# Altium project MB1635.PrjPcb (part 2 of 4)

## Sheet Power_Board.SchDoc: Board power
size A3; Project: STM32MP15-DISCO; Date: Not used; ApprovedBy: Not used; CheckedBy: Not used; Author: Not used; CompanyName: STMicroelectronics; DrawnBy: Not used; Engineer: Not used; Organization: Not used; Address1: Not used; Address2: Not used; Address3: Not used; Address4: Not used; DocumentNumber: 5; Revision: Not used; SheetNumber: 5; SheetTotal: 17

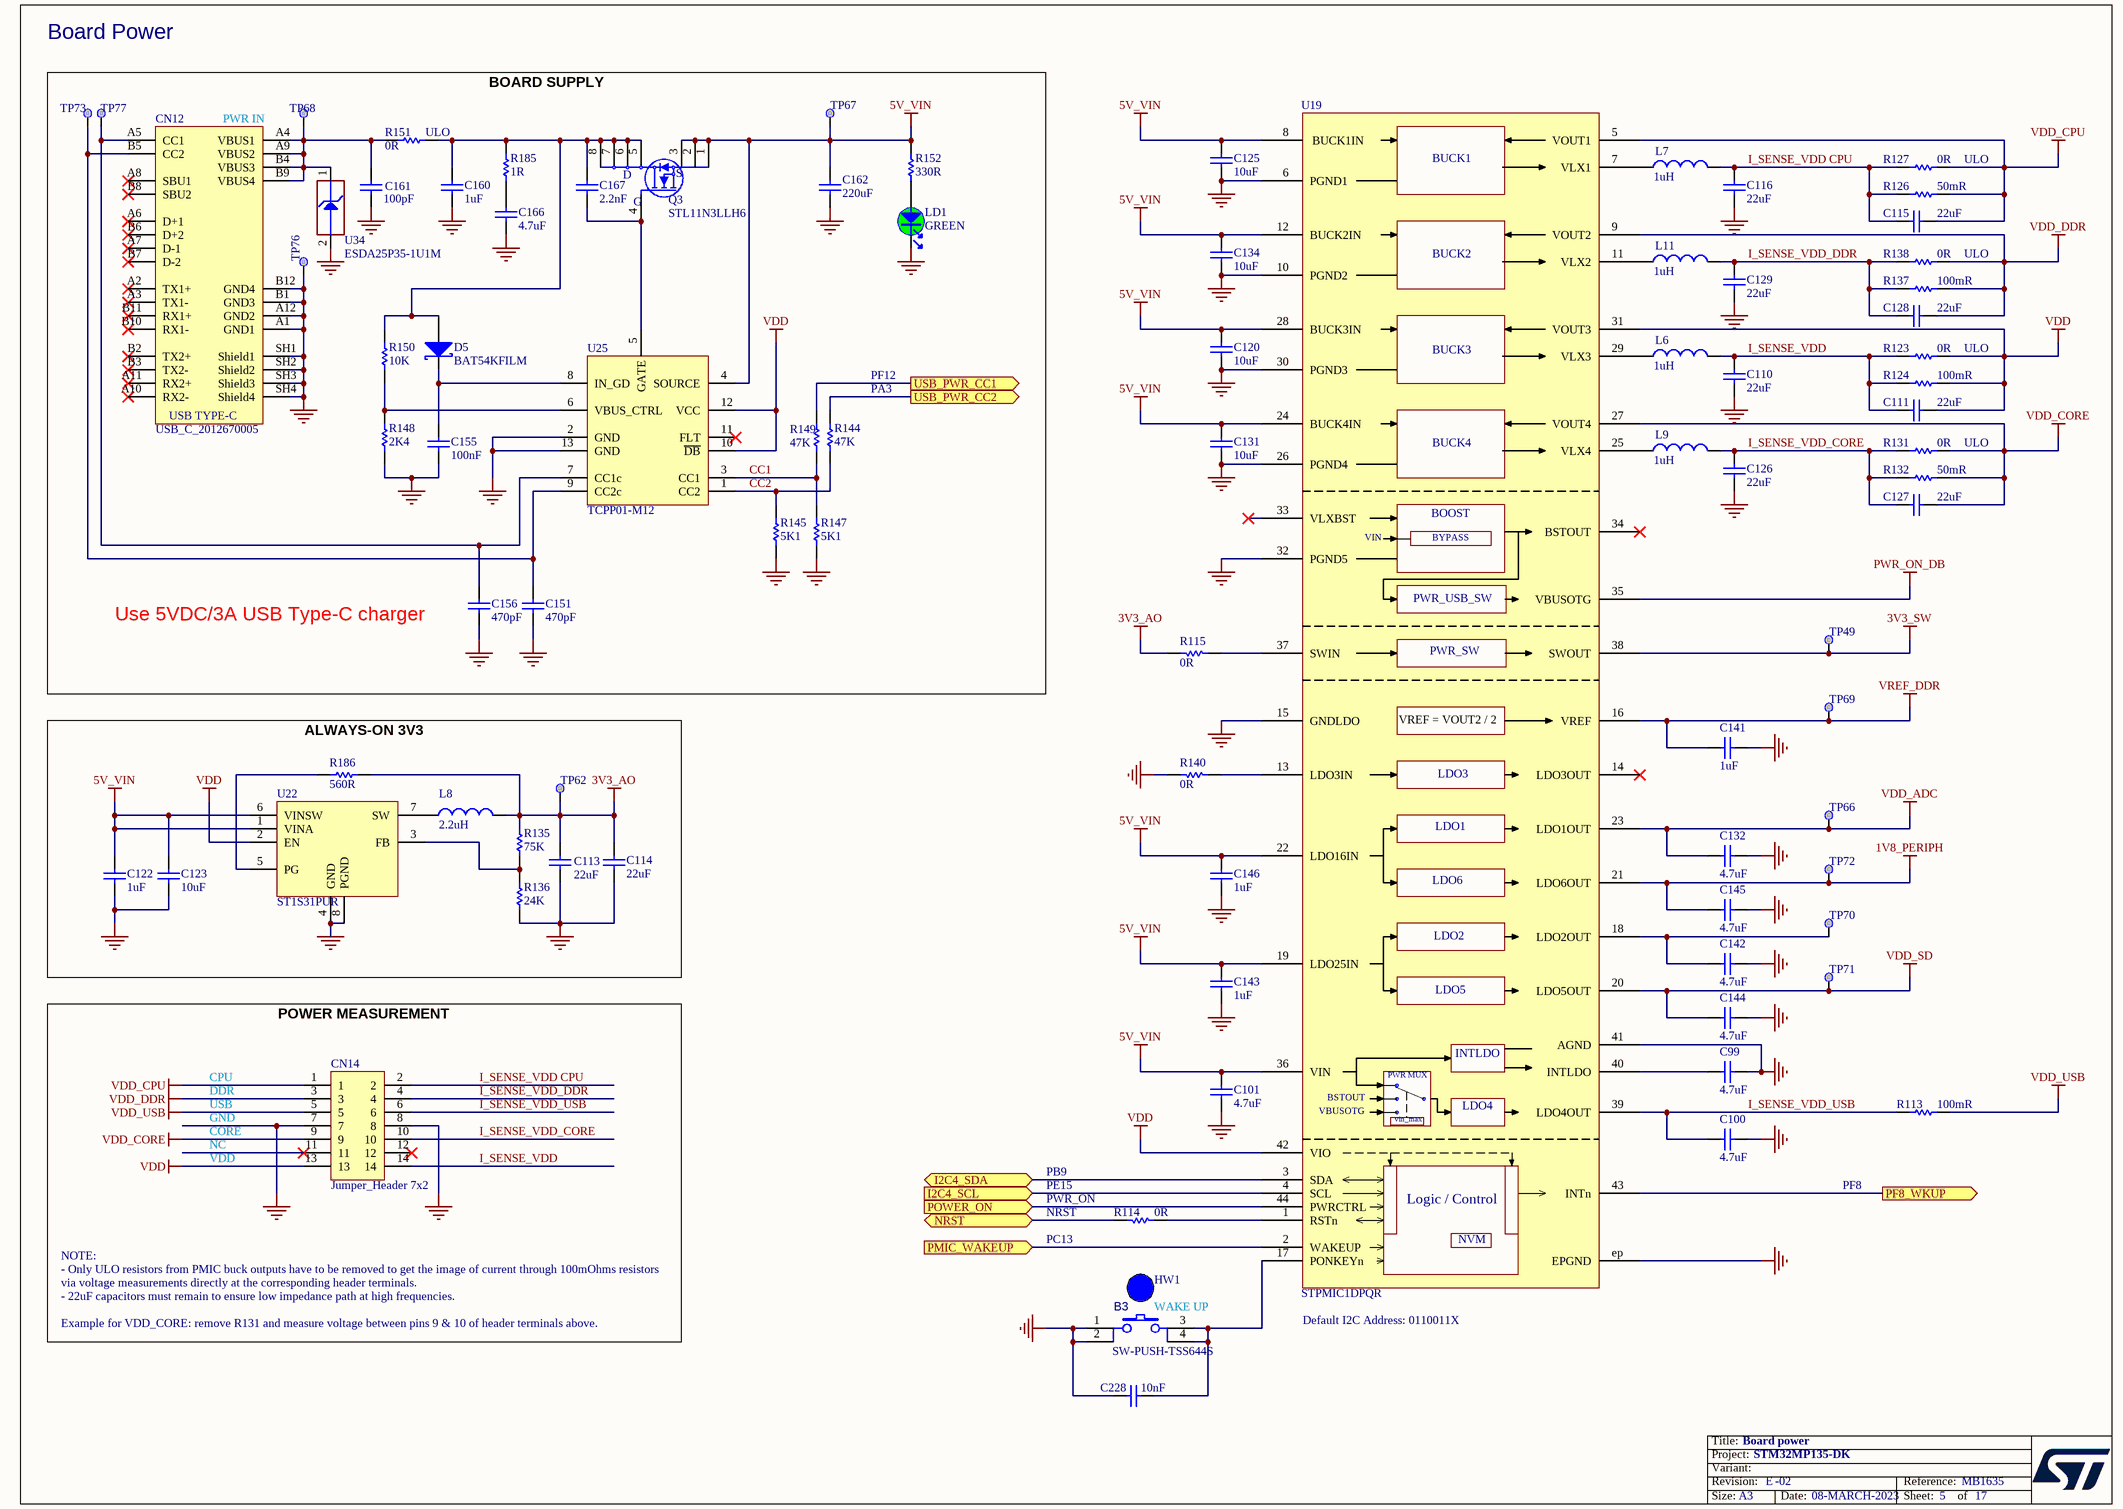
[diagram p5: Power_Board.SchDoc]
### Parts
B3  value SW-PUSH-TSS644S  [SWI_KNITTER_TSS644S]  (hidden comment: SW_PUSH_SMD)
C99  value 4.7uF  [C0402]  (hidden comment: Capacitor)
C100  value 4.7uF  [C0402]  (hidden comment: Capacitor)
C101  value 4.7uF  [C0402]  (hidden comment: Capacitor)
C110  value 22uF  [C0603]  (hidden comment: Capacitor)
C111  value 22uF  [C0603]  (hidden comment: Capacitor)
C113  value 22uF  [C0603]  (hidden comment: Capacitor)
C114  value 22uF  [C0603]  (hidden comment: Capacitor)
C115  value 22uF  [C0603]  (hidden comment: Capacitor)
C116  value 22uF  [C0603]  (hidden comment: Capacitor)
C120  value 10uF  [C0603]  (hidden comment: Capacitor)
C122  value 1uF  [C0402]  (hidden comment: Capacitor)
C123  value 10uF  [C0603]  (hidden comment: Capacitor)
C125  value 10uF  [C0603]  (hidden comment: Capacitor)
C126  value 22uF  [C0603]  (hidden comment: Capacitor)
C127  value 22uF  [C0603]  (hidden comment: Capacitor)
C128  value 22uF  [C0603]  (hidden comment: Capacitor)
C129  value 22uF  [C0603]  (hidden comment: Capacitor)
C131  value 10uF  [C0603]  (hidden comment: Capacitor)
C132  value 4.7uF  [C0402]  (hidden comment: Capacitor)
C134  value 10uF  [C0603]  (hidden comment: Capacitor)
C141  value 1uF  [C0402]  (hidden comment: Capacitor)
C142  value 4.7uF  [C0402]  (hidden comment: Capacitor)
C143  value 1uF  [C0402]  (hidden comment: Capacitor)
C144  value 4.7uF  [C0402]  (hidden comment: Capacitor)
C145  value 4.7uF  [C0402]  (hidden comment: Capacitor)
C146  value 1uF  [C0402]  (hidden comment: Capacitor)
C151  value 470pF  [C0402]  (hidden comment: Capacitor)
C155  value 100nF  [C0603]  (hidden comment: Capacitor)
C156  value 470pF  [C0402]  (hidden comment: Capacitor)
C160  value 1uF  [C0402]  (hidden comment: Capacitor)
C161  value 100pF  [C0402]  (hidden comment: Capacitor)
C162  value 220uF  [C1206_H1P6]  (hidden comment: Capacitor)
C166  value 4.7uF  [C0603]  (hidden comment: Capacitor)
C167  value 2.2nF  [C0603_H0P8]  (hidden comment: Capacitor)
C228  value 10nF  [C0402]  (hidden comment: Capacitor)
CN12  value USB_C_2012670005  [CON_USB-TYPEC_MOLEX_2012670005]  (hidden comment: USB_TYPE_C_Receptacle)
CN14  value Jumper_Header 7x2  [CON_SAMTEC_TSW-107-07-X-D]  (hidden comment: Header 7x2)
D5  value BAT54KFILM  [DIO_SOD523_1A_2K]  (hidden comment: SCHOTTKY_1A_2K)
HW1  Blue Hat  (value not drawn)  (mechanical)
L6  value 1uH  [IND_2520_TOKO_DFE252012P]  (hidden comment: IND_1uH_42mohm_3.2A)
L7  value 1uH  [IND_2520_TOKO_DFE252012P]  (hidden comment: IND_1uH_42mohm_3.2A)
L8  value 2.2uH  [IND_4025_WURTH_74404043022A]  (hidden comment: Inductor)
L9  value 1uH  [IND_2520_TOKO_DFE252012P]  (hidden comment: IND_1uH_42mohm_3.2A)
L11  value 1uH  [IND_2520_TOKO_DFE252012P]  (hidden comment: IND_1uH_42mohm_3.2A)
LD1  value GREEN  [LED_0603_GREEN]  (hidden comment: LED_green)
Q3  STL11N3LLH6  [MOS_POWERFLAT_3P3X3P3_P065]
R113  value 100mR  [R0603]  (hidden comment: Resistor)
R114  value 0R  [R0402]  (hidden comment: Resistor)
R115  value 0R  [R0402]  (hidden comment: Resistor)
R123  value 0R  [R0603]  (hidden comment: Resistor)
R124  value 100mR  [R0603]  (hidden comment: Resistor)
R126  value 50mR  [R0603]  (hidden comment: Resistor)
R127  value 0R  [R0603]  (hidden comment: Resistor)
R131  value 0R  [R0603]  (hidden comment: Resistor)
R132  value 50mR  [R0603]  (hidden comment: Resistor)
R135  value 75K  [R0402]  (hidden comment: Resistor)
R136  value 24K  [R0402]  (hidden comment: Resistor)
R137  value 100mR  [R0603]  (hidden comment: Resistor)
R138  value 0R  [R0603]  (hidden comment: Resistor)
R140  value 0R  [R0402]  (hidden comment: Resistor)
R144  value 47K  [R0402]  (hidden comment: Resistor)
R145  value 5K1  [R0402]  (hidden comment: Resistor)
R147  value 5K1  [R0402]  (hidden comment: Resistor)
R148  value 2K4  [R0402]  (hidden comment: Resistor)
R149  value 47K  [R0402]  (hidden comment: Resistor)
R150  value 10K  [R0402]  (hidden comment: Resistor)
R151  value 0R  [R0603]  (hidden comment: Resistor)
R152  value 330R  [R0402]  (hidden comment: Resistor)
R185  value 1R  [R0603]  (hidden comment: Resistor)
R186  value 560R  [R0402]  (hidden comment: Resistor)
TP49  Test Point  [TP_SMD_1MM]  (value not drawn)  (no BOM)
TP62  Test Point  [TP_SMD_1MM]  (value not drawn)  (no BOM)
TP66  Test Point  [TP_SMD_1MM]  (value not drawn)  (no BOM)
TP67  Test Point  [TP_SMD_1MM]  (value not drawn)  (no BOM)
TP68  Test Point  [TP_SMD_2MM]  (value not drawn)  (no BOM)
TP69  Test Point  [TP_SMD_1MM]  (value not drawn)  (no BOM)
TP70  Test Point  [TP_SMD_1MM]  (value not drawn)  (no BOM)
TP71  Test Point  [TP_SMD_1MM]  (value not drawn)  (no BOM)
TP72  Test Point  [TP_SMD_1MM]  (value not drawn)  (no BOM)
TP73  Test Point  [TP_SMD_1MM]  (value not drawn)  (no BOM)
TP76  Test Point  [TP_SMD_2MM]  (value not drawn)  (no BOM)
TP77  Test Point  [TP_SMD_1MM]  (value not drawn)  (no BOM)
U19  value STPMIC1DPQR  [ICC_WFQFN44-EPAD_5X6_P040]  (hidden comment: STPMU1)
U22  ST1S31PUR  [ICC_VFDFPN8-EPAD_3X3_P065]
U25  TCPP01-M12  [ICC_QFN12L-EPAD_3X3_P050]
U34  value ESDA25P35-1U1M  [ESD_QFN1610_2N_1K_2A]  (hidden comment: ESD-TRANSIL)

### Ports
I2C4_SCL (in), I2C4_SDA (bidir), NRST (bidir), PF8_WKUP (out), PMIC_WAKEUP (in), POWER_ON (in), USB_PWR_CC1 (out), USB_PWR_CC2 (out)

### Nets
1V8_PERIPH: C145.2 TP72.1 U19.21(LDO6OUT)
3V3_AO: C113.2 C114.2 L8.2 R115.1 R135.2 R186.2 TP62.1
3V3_SW: TP49.1 U19.38(SWOUT)
5V_VIN: C101.2 C120.2 C122.2 C123.2 C125.2 C131.2 C134.2 C143.2 C146.2 C162.1 Q3.1(S) Q3.2(S) Q3.3(S) R152.2 TP67.1 U19.8(BUCK1IN) U19.12(BUCK2IN) U19.19(LDO25IN) U19.22(LDO16IN) U19.24(BUCK4IN) U19.28(BUCK3IN) U19.36(VIN) U22.1(VINA) U22.6(VINSW) U25.4(SOURCE)
GND: B3.1 B3.2 C99.2 C100.1 C101.1 C110.1 C113.1 C114.1 C116.1 C120.1 C122.1 C123.1 C125.1 C126.1 C129.1 C131.1 C132.1 C134.1 C141.1 C142.1 C143.1 C144.1 C145.1 C146.1 C151.1 C155.2 C156.1 C160.2 C161.1 C162.2 C166.1 C228.1 CN12.A1(GND1) CN12.A12(GND2) CN12.B1(GND3) CN12.B12(GND4) CN12.SH1(Shield1) CN12.SH2(Shield2) CN12.SH3(Shield3) CN12.SH4(Shield4) CN14.7 CN14.8 LD1.2 R136.1 R140.1 R145.1 R147.1 R148.1 TP76.1 U19.6(PGND1) U19.10(PGND2) U19.15(GNDLDO) U19.26(PGND4) U19.30(PGND3) U19.32(PGND5) U19.41(AGND) U19.ep(EPGND) U22.4(GND) U22.8(PGND) U25.2(GND) U25.13(GND) U34.2(GND)
PWR_ON_DB: U19.35(VBUSOTG)
VDD: C111.2 CN14.13 R123.2 R124.2 U19.31(VOUT3) U19.42(VIO) U22.2(EN) U25.10(~{DB}) U25.12(VCC)
VDD_ADC: C132.2 TP66.1 U19.23(LDO1OUT)
VDD_CORE: C127.2 CN14.9 R131.2 R132.2 U19.27(VOUT4)
VDD_CPU: C115.2 CN14.1 R126.2 R127.2 U19.5(VOUT1)
VDD_DDR: C128.2 CN14.3 R137.2 R138.2 U19.9(VOUT2)
VDD_SD: C144.2 TP71.1 U19.20(LDO5OUT)
VDD_USB: CN14.5 R113.2
VREF_DDR: C141.2 TP69.1 U19.16(VREF)
CC1: R147.2 R149.1 U25.3(CC1)
CC2: R144.1 R145.2 U25.1(CC2)
I2C4_SCL: U19.4(SCL) ; port I2C4_SCL
I2C4_SDA: U19.3(SDA) ; port I2C4_SDA
I_SENSE_VDD: C110.2 C111.1 CN14.14 L6.2 R123.1 R124.1
I_SENSE_VDD CPU: C115.1 C116.2 CN14.2 L7.2 R126.1 R127.1
I_SENSE_VDD_CORE: C126.2 C127.1 CN14.10 L9.2 R131.1 R132.1
I_SENSE_VDD_DDR: C128.1 C129.2 CN14.4 L11.2 R137.1 R138.1
I_SENSE_VDD_USB: C100.2 CN14.6 R113.1 U19.39(LDO4OUT)
NRST: R114.1 ; port NRST
PF8_WKUP: U19.43(INTn) ; port PF8_WKUP
PMIC_WAKEUP: U19.2(WAKEUP) ; port PMIC_WAKEUP
POWER_ON: U19.44(PWRCTRL) ; port POWER_ON
USB_PWR_CC1: R149.2 ; port USB_PWR_CC1
USB_PWR_CC2: R144.2 ; port USB_PWR_CC2
NetB3_3: B3.3 B3.4 C228.2 U19.17(PONKEYn)
NetC99_1: C99.1 U19.40(INTLDO)
NetC142_2: C142.2 TP70.1 U19.18(LDO2OUT)
NetC151_2: C151.2 CN12.B5(CC2) TP73.1 U25.9(CC2c)
NetC155_1: C155.1 D5.2(K) U25.8(IN_GD)
NetC156_2: C156.2 CN12.A5(CC1) TP77.1 U25.7(CC1c)
NetC160_1: C160.1 C167.2 D5.1(A) Q3.5(D) Q3.6(D) Q3.7(D) Q3.8(D) R150.2 R151.2 R185.2
NetC161_2: C161.2 CN12.A4(VBUS1) CN12.A9(VBUS2) CN12.B4(VBUS3) CN12.B9(VBUS4) R151.1 TP68.1 U34.1(IO1)
NetC166_2: C166.2 R185.1
NetC167_1: C167.1 Q3.4(G) U25.5(GATE)
NetL6_1: L6.1 U19.29(VLX3)
NetL7_1: L7.1 U19.7(VLX1)
NetL8_1: L8.1 U22.7(SW)
NetL9_1: L9.1 U19.25(VLX4)
NetL11_1: L11.1 U19.11(VLX2)
NetLD1_1: LD1.1 R152.1
NetR114_2: R114.2 U19.1(RSTn)
NetR115_2: R115.2 U19.37(SWIN)
NetR135_1: R135.1 R136.2 U22.3(FB)
NetR140_2: R140.2 U19.13(LDO3IN)
NetR148_2: R148.2 R150.1 U25.6(VBUS_CTRL)
NetR186_1: R186.1 U22.5(PG)

Not connected (* = marked no-connect by the designer): CN12 A2(TX1+)* A3(TX1-)* A6(D+1)* A7(D-1)* A8(SBU1)* A10(RX2-)* A11(RX2+)* B2(TX2+)* B3(TX2-)* B6(D+2)* B7(D-2)* B8(SBU2)* B10(RX1-)* B11(RX1+)*; CN14 11* 12*; U19 14(LDO3OUT)* 33(VLXBST)* 34(BSTOUT)*; U25 11(FLT)*

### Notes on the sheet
- Board Power
- (near CN12) PWR IN
- (near R151) ULO
- ULO
- PF12
- PA3
- Use 5VDC/3A USB Type-C charger
- BOARD SUPPLY
- ALWAYS-ON 3V3
- CPU
- DDR
- USB
- GND
- VDD
- CORE
- NC
- PB9
- PE15
- PF8
- NRST
- (near R114) PWR_ON
- PC13
- NOTE:
  - Only ULO resistors from PMIC buck outputs have to be removed to get the image of current through 100mOhms resistors via voltage measurements directly at the corresponding header terminals.
  - 22uF capacitors must remain to ensure low impedance path at high frequencies.
  Example for VDD_CORE: remove R131 and measure voltage between pins 9 & 10 of header terminals above.
- (near B3) WAKE UP
- Default I2C Address: 0110011X
- (near CN14) POWER MEASUREMENT

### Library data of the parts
B3 = MCD-02417: Push Button, NO, 0.05A, 12V, 2.6N, SMD, 9.0x6.2mm, T=7.3mm, changeable caps KTSC-6xx; Part_Type: Misc; Manufacturer_Part_Number: TSS644S; Manufacturer: KNITTER-SWITCH; Part_Preference: Recommended; Component_Country_Of_Origin: China; ShowFields: YES; ID: 4523
C99-C101 C132 C142 C144 C145 = MCD-01356: Capacitor, MLCC, 4.7uF, 6V3, X5R, +/-20%, 0402, T=0.5mm; Manufacturer_Part_Number: GRM155R60J475ME47; Manufacturer: MURATA; Part_Preference: Recommended; Order_Code_RS: 814-5230; Component_Country_Of_Origin: Japan; ShowFields: YES; ID: 3456
C110 C116 C126 C129 = MCD-00100: Capacitor, MLCC, 22uF, 6V3, X5R, +/-20%, 0603, T=0.8mm; Manufacturer_Part_Number: GRM188R60J226MEA0J; Manufacturer: MURATA; Part_Preference: Recommended; Component_Country_Of_Origin: Japan; ShowFields: YES; ID: 2766
C111 C113-C115 C127 C128 = MCD-00100: Capacitor, MLCC, 22uF, 6V3, X5R, +/-20%, 0603, T=0.8mm; Part_Preference: Recommended; Manufacturer: MURATA; Manufacturer_Part_Number: GRM188R60J226MEA0J; Component_Country_Of_Origin: Japan; ShowFields: YES; ID: 2766
C120 C125 C131 C134 = MCD-00099: Capacitor, MLCC, 10uF, 10V, X5R, +/-10%, 0603, T=0.8mm; Manufacturer_Part_Number: GRM188R61A106KE69D; Manufacturer: MURATA; Part_Preference: Recommended; Order_Code_RS: 170-6168; Component_Country_Of_Origin: Japan; ShowFields: YES; ID: 2770
C122 = MCD-00095: Capacitor, MLCC, 1uF, 25V, X5R, +/-10%, 0402, T=0.5mm; Part_Preference: Recommended; Manufacturer: MURATA; Manufacturer_Part_Number: GRM155R61E105KA12; Order_Code_RS: 846-7287; Component_Country_Of_Origin: Japan; ShowFields: YES; ID: 2772
C123 = MCD-00099: Capacitor, MLCC, 10uF, 10V, X5R, +/-10%, 0603, T=0.8mm; Part_Preference: Recommended; Manufacturer: MURATA; Manufacturer_Part_Number: GRM188R61A106KE69D; Order_Code_RS: 170-6168; Component_Country_Of_Origin: Japan; ShowFields: YES; ID: 2770
C141 C143 C146 C160 = MCD-00095: Capacitor, MLCC, 1uF, 25V, X5R, +/-10%, 0402, T=0.5mm; Manufacturer_Part_Number: GRM155R61E105KA12; Manufacturer: MURATA; Part_Preference: Recommended; Order_Code_RS: 846-7287; Component_Country_Of_Origin: Japan; ShowFields: YES; ID: 2772
C151 C156 = MCD-00724: Capacitor, MLCC, 470pF, 50V, NPO, +/-5%, 0402, T=0.5mm; Manufacturer_Part_Number: CC0402JRNPO9BN471; Manufacturer: YAGEO; Part_Preference: Recommended; Order_Code_RS: 199-2186; Component_Country_Of_Origin: China; ShowFields: YES; ID: 3023
C155 = MCD-01099: Capacitor, MLCC, 100nF, 50V, X7R, +/-10%, 0603, T=0.8mm; Manufacturer_Part_Number: CC0603KRX7R9BB104; Manufacturer: YAGEO; Part_Preference: Recommended; BMS_Part_Number: 9142278; Order_Code_RS: 669-8767; Component_Country_Of_Origin: China; ShowFields: YES; ID: 3397
C161 = MCD-00205: Capacitor, MLCC, 100pF, 50V, NPO, +/-5%, 0402, T=0.5mm; Manufacturer_Part_Number: CC0402JRNPO9BN101; Manufacturer: YAGEO; Part_Preference: Recommended; Component_Country_Of_Origin: China; ShowFields: YES; ID: 2658
C162 = MCD-00104: Capacitor, MLCC, 220uF, 6V3, X5R, +/-20%, 1206, T=1.6mm; Manufacturer_Part_Number: GRM31CR60J227ME11; Manufacturer: MURATA; Part_Preference: Recommended; Order_Code_RS: 170-6396; Component_Country_Of_Origin: Japan; ShowFields: YES; ID: 2764
C166 = MCD-02196: Capacitor, MLCC, 4.7uF, 25V, X5R, +/-10%, 0603, T=0.8mm; Manufacturer_Part_Number: C1608X5R1E475K080AC; Manufacturer: TDK; Part_Preference: Recommended; Order_Code_RS: 9159158; Component_Country_Of_Origin: Unknown; ShowFields: YES; ID: 4296
C167 = MCD-02457: Capacitor, MLCC, 2.2nF, 50V, C0G/NPO, +/-5%, 0603, T=0,8mm; Part_Preference: Recommended; Manufacturer: YAGEO; Manufacturer_Part_Number: CC0603JRNPO9BN222; Order_Code_RS: 200-6484; Component_Country_Of_Origin: China; ShowFields: YES; ID: 4563
C228 = MCD-02198: Capacitor, MLCC, 10nF, 50V, X7R, +/-10%, 0402, T=0.5mm; Manufacturer_Part_Number: CC0402KRX7R9BB103; Manufacturer: YAGEO; Part_Preference: Recommended; Order_Code_RS: 6169644; Component_Country_Of_Origin: China; ShowFields: YES; ID: 4298
CN12 = MCD-02421: USB_TypeC, 24 pins, RA, SMD, T=3.71mm (USB Certified 3.1); Part_Type: Connector; Manufacturer_Part_Number: 2012670005; Manufacturer: MOLEX; Part_Preference: Recommended; Order_Code_RS: 176-8434; Component_Country_Of_Origin: Unknown; ShowFields: YES; ID: 4527
CN14 = MCD-02123: Header, 7x2, 2.54mm, VR, TH, T=5.84mm/2.54mm; Part_Preference: Recommended; Part_Type: Connector; Manufacturer: SAMTEC; Manufacturer_Part_Number: TSW-107-07-G-D; Component_Country_Of_Origin: China, Costa Rica, Malaysia, United States, Vietnam; ShowFields: YES; ID: 4223
D5 = MCD-01677: Small signal Schottky diodes; BMS_Part_Number: 9151123; Part_Preference: Recommended; Part_Type: Diode; Manufacturer: STMICROELECTRONICS; Manufacturer_HQ_COO: EU; Component_Country_Of_Origin: China; ShowFields: YES; ID: 3777
HW1 = MCD-02136: Switch hat, blue, For KTSC-62B; Part_Type: Misc; Part_Preference: Recommended; Manufacturer: APEM INC; Manufacturer_Part_Number: AKTSC62B; Order_Code_RS: 378-6779; Component_Country_Of_Origin: Unknown; ShowFields: YES; ID: 4236
L6 L7 L9 L11 = MCD-01122: Inductor, 1uH, +/-20%, 4.3A max, 0R042, 2520, T=1.2mm; Manufacturer_Part_Number: DFE252012P-1ROM=P2; Manufacturer: MURATA; Part_Preference: Recommended; Component_Country_Of_Origin: Japan; ShowFields: YES; ID: 3373
L8 = MCD-02242: Inductor, 2.2uH, +/-30%, 3,83A, 0R023, 4x4mm, T=2.5mm; Part_Preference: Recommended; Manufacturer: WURTH ELEKTRONIK; Manufacturer_Part_Number: 74404043022A; Component_Country_Of_Origin: Unknown; ShowFields: YES; ID: 4342
LD1 = MCD-00050: LED, Green, 0603; Part_Type: Display; Manufacturer_Part_Number: 19-213SYGC/S530-E2/TR8; Manufacturer: EVERLIGHT; Part_Preference: Forbidden; Component_Country_Of_Origin: China; ShowFields: YES; ID: 2542
Q3 = MCD-01810: N-channel 30 V, 6 mΩ typ, 11 A STripFET™ H6, Power MOSFET in a PowerFLAT™ 3.3x3.3 package; Part_Type: IC; Manufacturer: STMICROELECTRONICS; BMS_Part_Number: 9153561; Part_Preference: Recommended; Manufacturer_HQ_COO: EU; Component_Country_Of_Origin: China; ShowFields: YES; ID: 3910
R113 R124 R137 = MCD-02234: Resistor, 100mR, 0603, +/- 1%, 1/3W; Part_Preference: Recommended; Manufacturer: PANASONIC; Manufacturer_Part_Number: ERJ-3BWFR100V; Order_Code_RS: 763-8731; Component_Country_Of_Origin: Japan; ShowFields: YES; ID: 4334
R114 R115 R140 = MCD-00052: Resistor, 0R, 0402, +/-5%, 1/16W; Manufacturer_Part_Number: RC0402JR-070RL; Manufacturer: YAGEO; Part_Preference: Recommended; Order_Code_RS: 618-5804; Component_Country_Of_Origin: China; ShowFields: YES; ID: 2540
R123 R127 R131 R138 = MCD-00181: Resistor, 0R, 0603, +/- 0.5mR, 1/4W; Part_Preference: Recommended; Manufacturer: ROHM; Manufacturer_Part_Number: PMR03EZPJ000; Component_Country_Of_Origin: Philippines, Thailand; ShowFields: YES; ID: 2691
R126 R132 = MCD-02233: Resistor, 50mR, 0603, +/-1%, 1/3W; Part_Preference: Recommended; Manufacturer: PANASONIC; Manufacturer_Part_Number: ERJ-3BWFR050V; Order_Code_RS: RA; Component_Country_Of_Origin: Japan; ShowFields: YES; ID: 4333
R135 = MCD-00521: Resistor, 75K, 0402, +/-1%, 1/16W; Part_Preference: Recommended; Manufacturer: YAGEO; Manufacturer_Part_Number: RC0402FR-0775KL; Component_Country_Of_Origin: China; ShowFields: YES; ID: 3220
R136 = MCD-00435: Resistor, 24K, 0402, +/-1%, 1/16W; Part_Preference: Recommended; Manufacturer: YAGEO; Manufacturer_Part_Number: RC0402FR-0724KL; Component_Country_Of_Origin: China; ShowFields: YES; ID: 2845
R144 R149 = MCD-00063: Resistor, 47K, 0402, +/-1%, 1/16W; Manufacturer_Part_Number: RC0402FR-0747KL; Manufacturer: YAGEO; Part_Preference: Recommended; Component_Country_Of_Origin: China; ShowFields: YES; ID: 2528
R145 R147 = MCD-00333: Resistor, 5K1, 0402, +/-1%, 1/16W; Manufacturer_Part_Number: RC0402FR-075K1L; Manufacturer: YAGEO; Part_Preference: Recommended; Component_Country_Of_Origin: China; ShowFields: YES; ID: 2944
R148 = MCD-00433: Resistor, 2K4, 0402, +/-1%, 1/16W; Part_Preference: Recommended; Manufacturer: YAGEO; Manufacturer_Part_Number: RC0402FR-072K4L; Component_Country_Of_Origin: China; ShowFields: YES; ID: 2843
R150 = MCD-00053: Resistor, 10K, 0402, +/-1%, 1/16W; BMS_Part_Number: 9131590; Part_Preference: Recommended; Manufacturer: YAGEO; Manufacturer_Part_Number: RC0402FR-0710KL; Component_Country_Of_Origin: China; ShowFields: YES; ID: 2539
R151 = MCD-00181: Resistor, 0R, 0603, +/- 0.5mR, 1/4W; Manufacturer_Part_Number: PMR03EZPJ000; Manufacturer: ROHM; Part_Preference: Recommended; Component_Country_Of_Origin: Philippines, Thailand; ShowFields: YES; ID: 2691
R152 = MCD-00062: Resistor, 330R, 0402, +/-1%, 1/16W; Manufacturer_Part_Number: RC0402FR-07330RL; Manufacturer: YAGEO; Part_Preference: Recommended; Component_Country_Of_Origin: China; ShowFields: YES; ID: 2529
R185 = MCD-01512: Resistor, 1R, 0603, +/-1%, 1/10W; Part_Preference: Recommended; Manufacturer: YAGEO; Manufacturer_Part_Number: RC0603FR-071RL; Component_Country_Of_Origin: China; ShowFields: YES; ID: 3612
R186 = MCD-00489: Resistor, 560R, 0402, +/-1%, 1/16W; Part_Preference: Recommended; Manufacturer: YAGEO; Manufacturer_Part_Number: RC0402FR-07560RL; Component_Country_Of_Origin: China; ShowFields: YES; ID: 2789
TP49 TP62 TP66 TP67 TP69-TP73 TP77 = MCD-00074: Test Point 1mm; Part_Type: Misc; Part_Preference: Recommended; ShowFields: YES; ID: 2518
TP68 TP76 = MCD-00177: Test Point 2mm; Part_Type: Misc; Part_Preference: Recommended; ShowFields: YES; ID: 2690
U19 = MCD-02275: ST PMIC: 4 step-down +1 advanced boost SMPS, 6 LDOs, 2 pwr switches, DDR Vref, NVM option 'D' for IO@3.3V; Part_Preference: Recommended; Part_Type: IC; Manufacturer: STMICROELECTRONICS; Component_Country_Of_Origin: Philippines; ShowFields: YES; ID: 4375
U22 = MCD-02243: 3A DC step-down switching regulator 1,5MHz; Part_Preference: Recommended; Part_Type: IC; Manufacturer: STMICROELECTRONICS; Manufacturer_HQ_COO: EU; Component_Country_Of_Origin: Malaysia; ShowFields: YES; ID: 4343
U25 = MCD-01809: USB Type-C Port Protection for USB Power Delivery, PPS compliant; BMS_Part_Number: 9151145; Part_Preference: Recommended; Part_Type: IC; Manufacturer: STMICROELECTRONICS; Manufacturer_HQ_COO: EU; Component_Country_Of_Origin: Malaysia; ShowFields: YES; ID: 3909
U34 = MCD-01207: High power Transient voltage suppressor:25V/35A EOS and ESD transients protection.; BMS_Part_Number: 9179045; Part_Preference: Recommended; Part_Type: Diode; Manufacturer: STMICROELECTRONICS; Manufacturer_HQ_COO: EU; Component_Country_Of_Origin: China; ShowFields: YES; ID: 3289

## Sheet ST-Link_V3E.SchDoc: ST-LINK V3E
size A3; Project: STLink V3 Embedded Prototype; BOM Version: A-01; Date: Not used; ApprovedBy: Not used; CheckedBy: Not used; Author: Not used; CompanyName: STMicroelectronics; DrawnBy: Not used; Engineer: Not used; Organization: Not used; Address1: Not used; Address2: Not used; Address3: Not used; Address4: Not used; DocumentNumber: 17; Revision: Not used; SheetNumber: 17; SheetTotal: 17

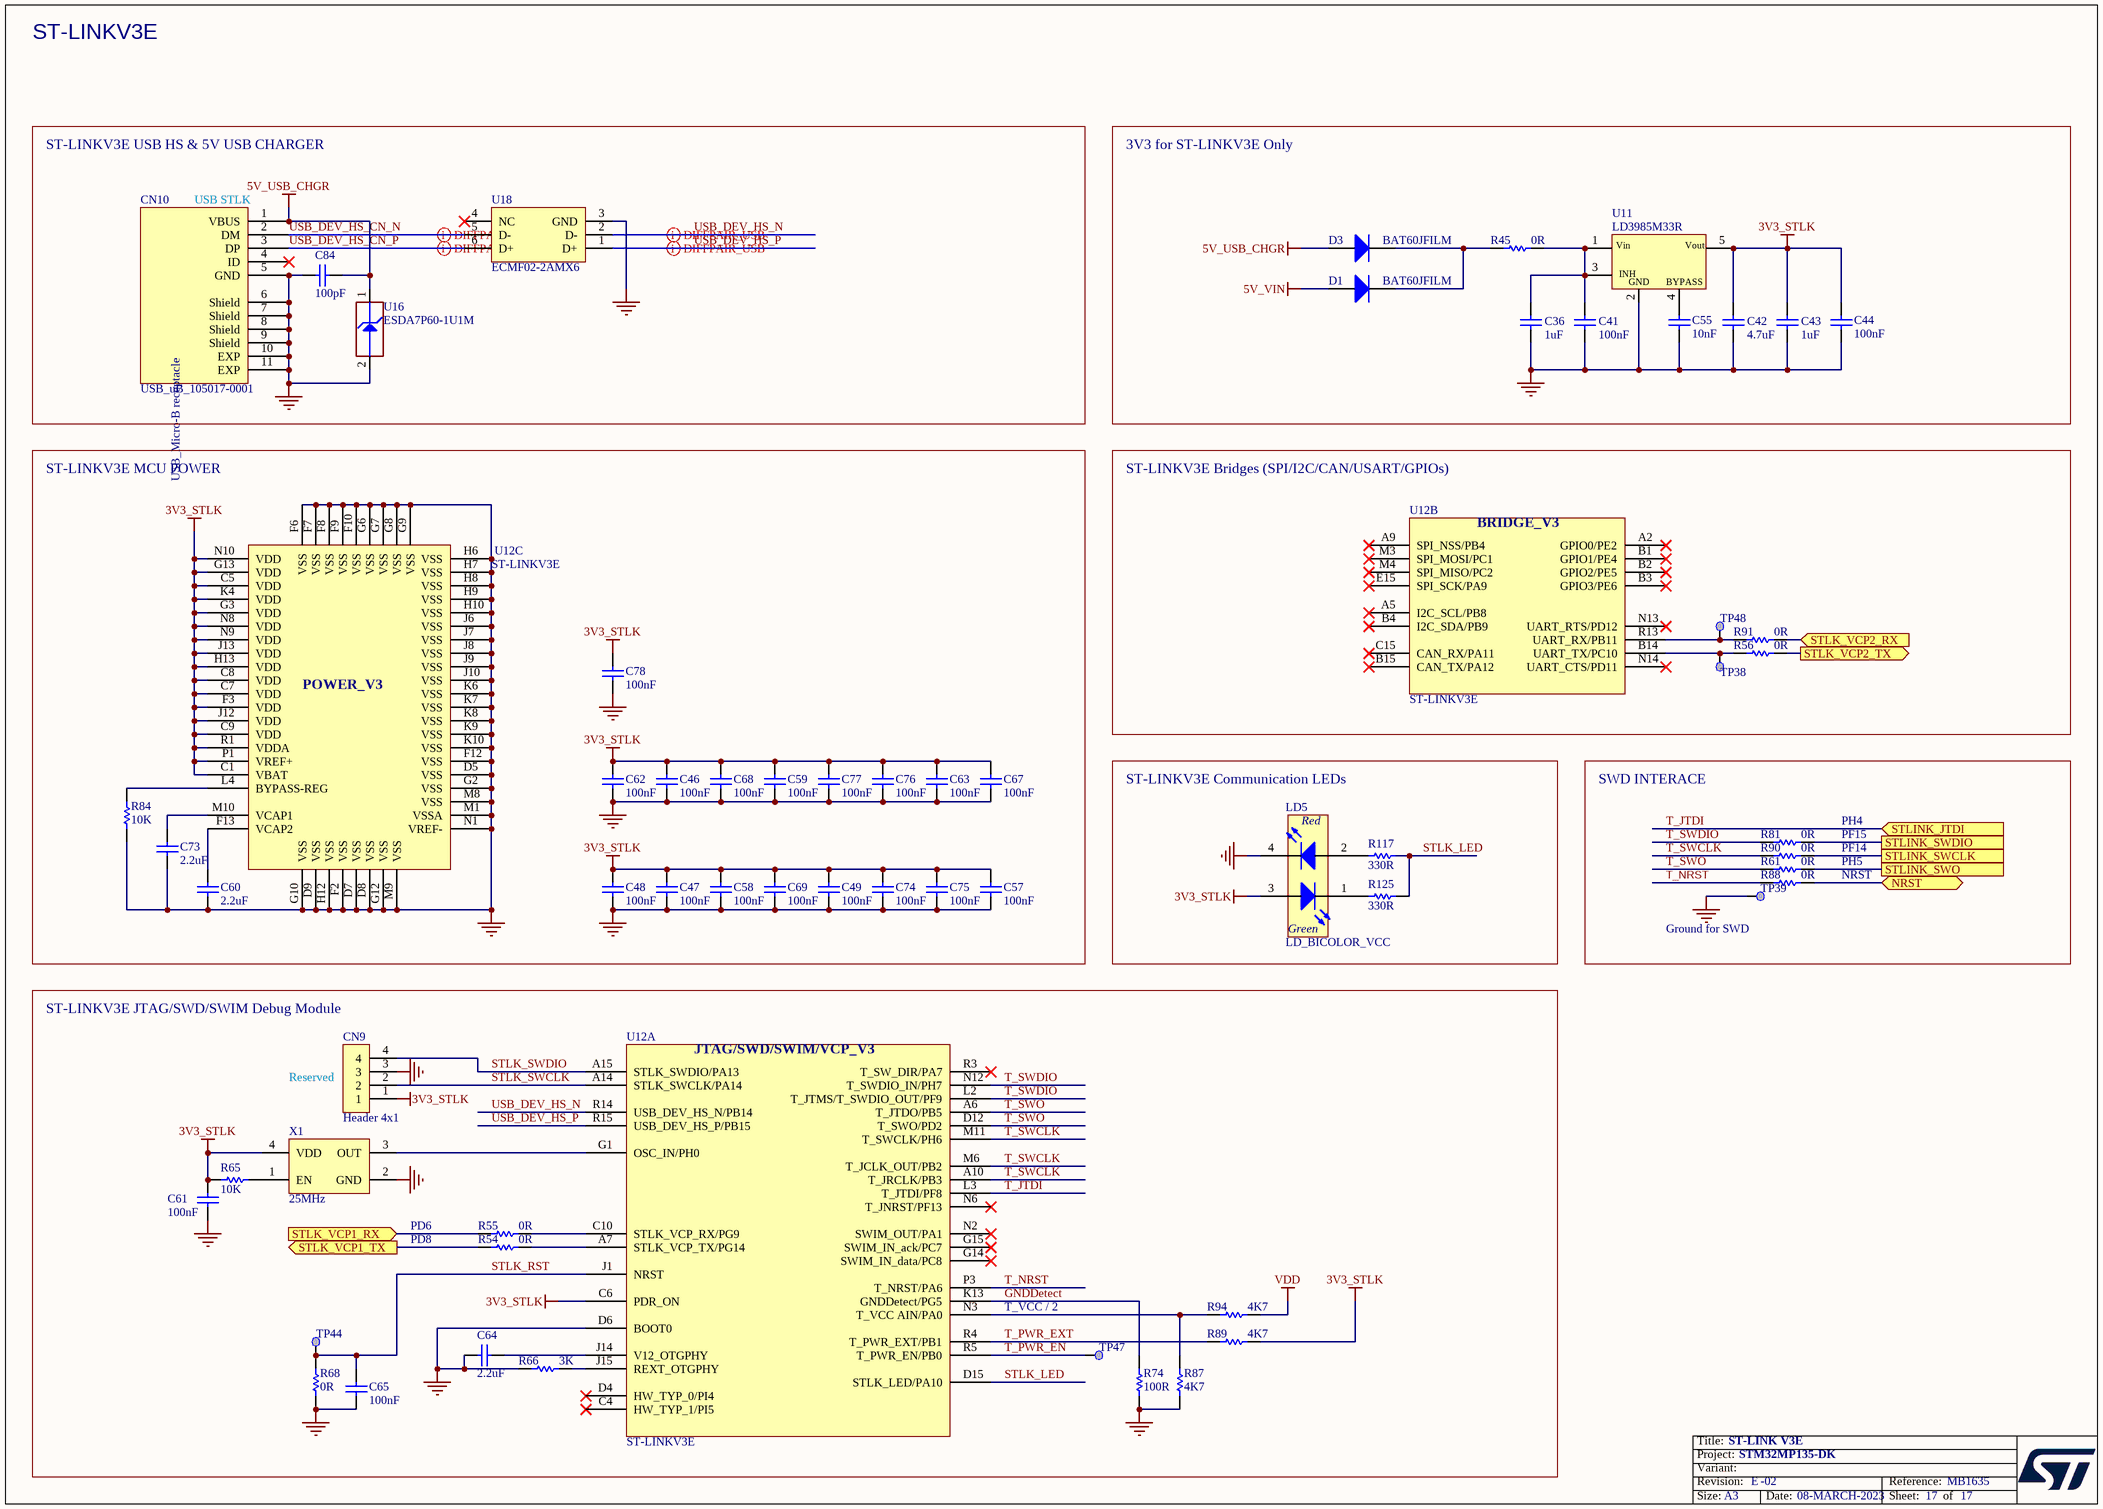
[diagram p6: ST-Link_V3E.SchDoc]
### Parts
C36  value 1uF  [C0402]  (hidden comment: Capacitor)
C41  value 100nF  [C0402]  (hidden comment: Capacitor)
C42  value 4.7uF  [C0402]  (hidden comment: Capacitor)
C43  value 1uF  [C0402]  (hidden comment: Capacitor)
C44  value 100nF  [C0402]  (hidden comment: Capacitor)
C46  value 100nF  [C0402]  (hidden comment: Capacitor)
C47  value 100nF  [C0402]  (hidden comment: Capacitor)
C48  value 100nF  [C0402]  (hidden comment: Capacitor)
C49  value 100nF  [C0402]  (hidden comment: Capacitor)
C55  value 10nF  [C0402]  (hidden comment: Capacitor)
C57  value 100nF  [C0402]  (hidden comment: Capacitor)
C58  value 100nF  [C0402]  (hidden comment: Capacitor)
C59  value 100nF  [C0402]  (hidden comment: Capacitor)
C60  value 2.2uF  [C0201_H0P5]  (hidden comment: Capacitor)
C61  value 100nF  [C0402]  (hidden comment: Capacitor)
C62  value 100nF  [C0402]  (hidden comment: Capacitor)
C63  value 100nF  [C0402]  (hidden comment: Capacitor)
C64  value 2.2uF  [C0201_H0P5]  (hidden comment: Capacitor)
C65  value 100nF  [C0402]  (hidden comment: Capacitor)
C67  value 100nF  [C0402]  (hidden comment: Capacitor)
C68  value 100nF  [C0402]  (hidden comment: Capacitor)
C69  value 100nF  [C0402]  (hidden comment: Capacitor)
C73  value 2.2uF  [C0201_H0P5]  (hidden comment: Capacitor)
C74  value 100nF  [C0402]  (hidden comment: Capacitor)
C75  value 100nF  [C0402]  (hidden comment: Capacitor)
C76  value 100nF  [C0402]  (hidden comment: Capacitor)
C77  value 100nF  [C0402]  (hidden comment: Capacitor)
C78  value 100nF  [C0402]  (hidden comment: Capacitor)
C84  value 100pF  [C0402]  (hidden comment: Capacitor)
CN9  Header 4x1  [CON_SAMTEC_TSW-104-07-G-S]
CN10  value USB_uB_105017-0001  [CON_USBMICROB_MOLEX_105017-0001_H2P90]  (hidden comment: USB_uB_105017.0001)
D1  BAT60JFILM  [DIO_SOD323]
D3  BAT60JFILM  [DIO_SOD323]
LD5  LD_BICOLOR_VCC  [LED_BI-GR_CMD67-22]
R45  value 0R  [R0402]  (hidden comment: Resistor)
R54  value 0R  [R0402]  (hidden comment: Resistor)
R55  value 0R  [R0402]  (hidden comment: Resistor)
R56  value 0R  [R0402]  (hidden comment: Resistor)
R61  value 0R  [R0402]  (hidden comment: Resistor)
R65  value 10K  [R0402]  (hidden comment: Resistor)
R66  value 3K  [R0402]  (hidden comment: Resistor)
R68  value 0R  [R0402]  (hidden comment: Resistor)
R74  value 100R  [R0402]  (hidden comment: Resistor)
R81  value 0R  [R0402]  (hidden comment: Resistor)
R84  value 10K  [R0402]  (hidden comment: Resistor)
R87  value 4K7  [R0402]  (hidden comment: Resistor)
R88  value 0R  [R0402]  (hidden comment: Resistor)
R89  value 4K7  [R0402]  (hidden comment: Resistor)
R90  value 0R  [R0402]  (hidden comment: Resistor)
R91  value 0R  [R0402]  (hidden comment: Resistor)
R94  value 4K7  [R0402]  (hidden comment: Resistor)
R117  value 330R  [R0402]  (hidden comment: Resistor)
R125  value 330R  [R0402]  (hidden comment: Resistor)
TP38  Test Point  [TP_SMD_1MM]  (value not drawn)  (no BOM)
TP39  Test Point  [TP_SMD_1MM]  (value not drawn)  (no BOM)
TP44  Test Point  [TP_SMD_1MM]  (value not drawn)  (no BOM)
TP47  Test Point  [TP_SMD_1MM]  (value not drawn)  (no BOM)
TP48  Test Point  [TP_SMD_1MM]  (value not drawn)  (no BOM)
U11  LD3985M33R  [REG_SOT23-5L]
U12  ST-LINKV3E  [ICC_UFBGA201_176+25_10X10_P065]  (parts A,B,C of 3)
U16  value ESDA7P60-1U1M  [ESD_QFN2_1P6X1_P125]  (hidden comment: ESD-TRANSIL)
U18  ECMF02-2AMX6  [ESD_QFN-6L_1P7X1P5_P050]
X1  value 25MHz  [OSC_NDK_NZ2520SB_4P]  (hidden comment: OSCILLATOR_4_PINS)

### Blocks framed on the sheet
ST-LINKV3E USB HS & 5V USB CHARGER: C84 CN10 U16 U18
3V3 for ST-LINKV3E Only: C36 C41-C44 C55 D1 D3 R45 U11
ST-LINKV3E MCU POWER: C46-C49 C57-C60 C62 C63 C67-C69 C73-C78 R84 U12
ST-LINKV3E Bridges (SPI/I2C/CAN/USART/GPIOs): R56 R91 TP38 TP48 U12
ST-LINKV3E Communication LEDs: LD5 R117 R125
SWD INTERACE: R61 R81 R88 R90 TP39
ST-LINKV3E JTAG/SWD/SWIM Debug Module: C61 C64 C65 CN9 R54 R55 R65 R66 R68 R74 R87 R89 R94 TP44 TP47 U12 X1

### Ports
NRST (bidir), STLINK_JTDI (in), STLINK_SWCLK, STLINK_SWDIO, STLINK_SWO, STLK_VCP1_RX (in), STLK_VCP1_TX (out), STLK_VCP2_RX (in), STLK_VCP2_TX (out)

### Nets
3V3_STLK: C42.2 C43.2 C44.2 C46.2 C47.2 C48.2 C49.2 C57.2 C58.2 C59.2 C61.2 C62.2 C63.2 C67.2 C68.2 C69.2 C74.2 C75.2 C76.2 C77.2 C78.2 CN9.1 LD5.3(YellowGreen_anode) R65.1 R89.1 U11.5(Vout) U12.C1(VBAT) U12.C5(VDD) U12.C6(PDR_ON) U12.C7(VDD) U12.C8(VDD) U12.C9(VDD) U12.F3(VDD) U12.G3(VDD) U12.G13(VDD) U12.H13(VDD) U12.J12(VDD) U12.J13(VDD) U12.K4(VDD) U12.N8(VDD) U12.N9(VDD) U12.N10(VDD) U12.P1(VREF+) U12.R1(VDDA) X1.4(VDD)
5V_USB_CHGR: C84.2 CN10.1(VBUS) D3.1(A) U16.1(IO1)
5V_VIN: D1.1(A)
GND: C36.2 C41.1 C42.1 C43.1 C44.1 C46.1 C47.1 C48.1 C49.1 C55.1 C57.1 C58.1 C59.1 C60.1 C61.1 C62.1 C63.1 C64.1 C65.1 C67.1 C68.1 C69.1 C73.1 C74.1 C75.1 C76.1 C77.1 C78.1 C84.1 CN9.3 CN10.5(GND) CN10.6(Shield) CN10.7(Shield) CN10.8(Shield) CN10.9(Shield) CN10.10(EXP) CN10.11(EXP) LD5.4(RED_cathode) R66.1 R68.2 R74.1 R84.1 R87.1 TP39.1 U11.2(GND) U12.D5(VSS) U12.D6(BOOT0) U12.D7(VSS) U12.D8(VSS) U12.D9(VSS) U12.F2(VSS) U12.F6(VSS) U12.F7(VSS) U12.F8(VSS) U12.F9(VSS) U12.F10(VSS) U12.F12(VSS) U12.G2(VSS) U12.G6(VSS) U12.G7(VSS) U12.G8(VSS) U12.G9(VSS) U12.G10(VSS) U12.G12(VSS) U12.H6(VSS) U12.H7(VSS) U12.H8(VSS) U12.H9(VSS) U12.H10(VSS) U12.H12(VSS) U12.J6(VSS) U12.J7(VSS) U12.J8(VSS) U12.J9(VSS) U12.J10(VSS) U12.K6(VSS) U12.K7(VSS) U12.K8(VSS) U12.K9(VSS) U12.K10(VSS) U12.M1(VSSA) U12.M8(VSS) U12.M9(VSS) U12.N1(VREF-) U16.2(GND) U18.3(GND) X1.2(GND)
VDD: R94.2
GNDDetect: R74.2 U12.K13(GNDDetect/PG5)
NRST: R88.2 ; port NRST
STLINK_SWCLK: R90.2 ; port STLINK_SWCLK
STLINK_SWDIO: R81.2 ; port STLINK_SWDIO
STLINK_SWO: R61.2 ; port STLINK_SWO
STLK_LED: R117.2 R125.2 U12.D15(STLK_LED/PA10)
STLK_RST: C65.2 R68.1 TP44.1 U12.J1(NRST)
STLK_SWCLK: CN9.2 U12.A14(STLK_SWCLK/PA14)
STLK_SWDIO: CN9.4 U12.A15(STLK_SWDIO/PA13)
STLK_VCP1_RX: R55.2 ; port STLK_VCP1_RX
STLK_VCP1_TX: R54.2 ; port STLK_VCP1_TX
STLK_VCP2_RX: R91.1 ; port STLK_VCP2_RX
STLK_VCP2_TX: R56.1 ; port STLK_VCP2_TX
T_JTDI: U12.L3(T_JTDI/PF8) ; port STLINK_JTDI
T_NRST: R88.1 U12.P3(T_NRST/PA6)
T_PWR_EN: TP47.1 U12.R5(T_PWR_EN/PB0)
T_PWR_EXT: R89.2 U12.R4(T_PWR_EXT/PB1)
T_SWCLK: R90.1 U12.A10(T_JRCLK/PB3) U12.M6(T_JCLK_OUT/PB2) U12.M11(T_SWCLK/PH6)
T_SWDIO: R81.1 U12.L2(T_JTMS/T_SWDIO_OUT/PF9) U12.N12(T_SWDIO_IN/PH7)
T_SWO: R61.1 U12.A6(T_JTDO/PB5) U12.D12(T_SWO/PD2)
USB_DEV_HS_CN_N: CN10.2(DM) U18.5(D-)
USB_DEV_HS_CN_P: CN10.3(DP) U18.6(D+)
USB_DEV_HS_N: U12.R14(USB_DEV_HS_N/PB14) U18.2(D-)
USB_DEV_HS_P: U12.R15(USB_DEV_HS_P/PB15) U18.1(D+)
NetC36_1: C36.1 C41.2 R45.2 U11.1(Vin) U11.3(CE)
NetC55_2: C55.2 U11.4(BYPASS)
NetC60_2: C60.2 U12.F13(VCAP2)
NetC64_2: C64.2 U12.J14(V12_OTGPHY)
NetC73_2: C73.2 U12.M10(VCAP1)
NetD1_2: D1.2(K) D3.2(K) R45.1
NetLD5_1: LD5.1(YellowGreen_cathode) R125.1
NetLD5_2: LD5.2(Red_anode) R117.1
NetR54_1: R54.1 U12.A7(STLK_VCP_TX/PG14)
NetR55_1: R55.1 U12.C10(STLK_VCP_RX/PG9)
NetR56_2: R56.2 TP38.1 U12.B14(UART_TX/PC10)
NetR65_2: R65.2 X1.1(EN)
NetR66_2: R66.2 U12.J15(REXT_OTGPHY)
NetR84_2: R84.2 U12.L4(BYPASS-REG)
NetR87_2: R87.2 R94.1 U12.N3(T_VCC_AIN/PA0)
NetR91_2: R91.2 TP48.1 U12.R13(UART_RX/PB11)
NetU12_G1: U12.G1(OSC_IN/PH0) X1.3(OUT)

Not connected (* = marked no-connect by the designer): CN10 4(ID)*; U12 A2(GPIO0/PE2)* A5(I2C_SCL/PB8)* A9(SPI_NSS/PB4)* B1(GPIO1/PE4)* B2(GPIO2/PE5)* B3(GPIO3/PE6)* B4(I2C_SDA/PB9)* B15(CAN_TX/PA12)* C4(HW_TYP_1/PI5)* C15(CAN_RX/PA11)* D4(HW_TYP_0/PI4)* E15(SPI_SCK/PA9)* G14(SWIM_IN_data/PC8)* G15(SWIM_IN_ack/PC7)* M3(SPI_MOSI/PC1)* M4(SPI_MISO/PC2)* N2(SWIM_OUT/PA1)* N6(T_JNRST/PF13)* N13(UART_RTS/PD12)* N14(UART_CTS/PD11)* R3(T_SW_DIR/PA7)*; U18 4(NC)*

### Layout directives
differential pair; rule Impedance Constraint [Min = 85.00    Max = 95.00    ]: USB_DEV_HS_CN_N, USB_DEV_HS_CN_P, USB_DEV_HS_N, USB_DEV_HS_P

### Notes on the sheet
- ST-LINKV3E
- (near CN10) USB STLK
- PF14
- PF15
- PH4
- NRST
- PH5
- Ground for SWD
- (near CN9) Reserved
- PD8
- PD6
- T_VCC / 2

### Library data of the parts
C36 C43 = MCD-00095: as C141 on sheet Power_Board
C41 C44 C46-C49 C57-C59 C61-C63 C67-C69 C74-C78 = MCD-00006: Capacitor, MLCC, 100nF, 16V, X7R, +/-10%, 0402, T=0.5mm; Manufacturer_Part_Number: CC0402KRX7R7BB104; Manufacturer: YAGEO; Part_Preference: Recommended; Order_Code_RS: 616-9701; Component_Country_Of_Origin: China; ShowFields: YES; ID: 2474
C42 = MCD-01356: as C99 on sheet Power_Board
C55 = MCD-02198: as C228 on sheet Power_Board
C60 C64 C73 = MCD-02235: Capacitor, MLCC, 2.2uF, 10V, X5R,+/-10%, 0201, T=0.5mm; Manufacturer_Part_Number: GRM033R61A225KE47D; Manufacturer: MURATA; Part_Preference: Recommended; Order_Code_RS: NA; Component_Country_Of_Origin: Japan; ShowFields: YES; ID: 4335
C65 = MCD-00006: Capacitor, MLCC, 100nF, 16V, X7R, +/-10%, 0402, T=0.5mm; Part_Preference: Recommended; Manufacturer: YAGEO; Manufacturer_Part_Number: CC0402KRX7R7BB104; Order_Code_RS: 616-9701; Component_Country_Of_Origin: China; ShowFields: YES; ID: 2474
C84 = MCD-00205: as C161 on sheet Power_Board
CN9 = MCD-00029: Header, 4x1, 2.54mm, VR, TH, T=5.84mm/2.54mm; Part_Type: Connector; Manufacturer_Part_Number: TSW-104-07-G-S; Manufacturer: SAMTEC; Part_Preference: Recommended; Order_Code_RS: 161-2261; Component_Country_Of_Origin: China, Costa Rica, Malaysia, United States, Vietnam; ShowFields: YES; ID: 2487
CN10 = MCD-00028: MicroUSB_TypeB, 5pins, 0.65mm, RA, SMD, T=2.9mm; Manufacturer_Part_Number: 1050170001; Manufacturer: MOLEX; Part_Type: Connector; Part_Preference: Recommended; Order_Code_RS: 848-6764; Component_Country_Of_Origin: Unknown; ShowFields: YES; ID: 2489
D1 D3 = MCD-00034: Manufacturer: STMICROELECTRONICS; Part_Type: Diode; BMS_Part_Number: 9151097; Part_Preference: Recommended; Manufacturer_HQ_COO: EU; Component_Country_Of_Origin: China; ShowFields: YES; ID: 2483
LD5 = MCD-02629: LED Bicolor, Green, Red, 4-PLCC; Part_Type: Display; Manufacturer_Part_Number: CMD6722VRVGCTR8; Manufacturer: VISUAL COMMUNICATIONS COMPANY - VCC; Part_Preference: Not recommended; ShowFields: YES; ID: 4735
R45 R61 R81 R88 R90 = MCD-00052: Resistor, 0R, 0402, +/-5%, 1/16W; Part_Preference: Recommended; Manufacturer: YAGEO; Manufacturer_Part_Number: RC0402JR-070RL; Order_Code_RS: 618-5804; Component_Country_Of_Origin: China; ShowFields: YES; ID: 2540
R54-R56 R68 R91 = MCD-00052: as R114 on sheet Power_Board
R65 R84 = MCD-00053: Resistor, 10K, 0402, +/-1%, 1/16W; Manufacturer_Part_Number: RC0402FR-0710KL; Manufacturer: YAGEO; BMS_Part_Number: 9131590; Part_Preference: Recommended; Component_Country_Of_Origin: China; ShowFields: YES; ID: 2539
R66 = MCD-00185: Resistor, 3K, 0402, +/-1%, 1/16W; Manufacturer_Part_Number: RC0402FR-073KL; Manufacturer: YAGEO; Part_Preference: Recommended; Component_Country_Of_Origin: China; ShowFields: YES; ID: 2682
R74 = MCD-00067: Resistor, 100R, 0402, +/- 1%, 1/16W; Manufacturer_Part_Number: RC0402FR-07100RL; Manufacturer: YAGEO; Part_Preference: Recommended; Component_Country_Of_Origin: China; ShowFields: YES; ID: 2527
R87 R89 R94 = MCD-00065: Resistor, 4K7, 0402, +/-1%, 1/16W; Manufacturer_Part_Number: RC0402FR-074K7L; Manufacturer: YAGEO; Part_Preference: Recommended; Component_Country_Of_Origin: China; ShowFields: YES; ID: 2526
R117 R125 = MCD-00062: as R152 on sheet Power_Board
TP38 TP39 TP44 TP47 TP48 = MCD-00074: as TP49 on sheet Power_Board
U11 = MCD-00086: Ultra low drop-low noise BiCMOS voltage, regulators low ESR capacitors compatible; BMS_Part_Number: 9176161; Part_Preference: Recommended; Part_Type: IC; Manufacturer: STMICROELECTRONICS; Manufacturer_HQ_COO: EU; Component_Country_Of_Origin: China; ShowFields: YES; ID: 2506
U12 = MCD-01523: MCU, Arm Cortex-M7 32-bit MCU, 512KB Flash, 276KB RAM, With Crypto; Part_Type: IC; Manufacturer_Part_Number: STM32F723IEK6; Manufacturer: STMICROELECTRONICS; Part_Preference: Recommended; Manufacturer_HQ_COO: EU; Value: ST-LINKV3S; Component_Country_Of_Origin: Philippines; ShowFields: YES; ID: 3623
U16 = MCD-00251: High power transient voltage suppressor, 7V breakdown; Part_Type: Diode; Manufacturer: STMICROELECTRONICS; BMS_Part_Number: 9179042; Part_Preference: Recommended; Manufacturer_HQ_COO: EU; Component_Country_Of_Origin: China; ShowFields: YES; ID: 2618
U18 = MCD-00649: Common mode filter with ESD protection for USB 2.0 interface; Part_Type: Diode; Manufacturer: STMICROELECTRONICS; BMS_Part_Number: 9151138; Part_Preference: Recommended; Manufacturer_HQ_COO: EU; Component_Country_Of_Origin: China; ShowFields: YES; ID: 3094
X1 = MCD-00597: Oscillator, SPXO, 25Mhz, +/-50ppm, 3V3, square wave, 2.5x2mm; Manufacturer_Part_Number: NZ2520SH-25MHZ-END4869C; Manufacturer: NDK; Part_Type: Crystal_Osc; BMS_Part_Number: 9157050; Part_Preference: Recommended; Component_Country_Of_Origin: Unknown; ShowFields: YES; ID: 3148

## Sheet WLAN_BLUETOOTH.SchDoc: WLAN & Bluetooth
size A4; Project: STM32MP15-DISCO PI; Date: Not used; ApprovedBy: Not used; CheckedBy: Not used; Author: Not used; CompanyName: STMicroelectronics; DrawnBy: Not used; Engineer: Not used; Organization: Not used; Address1: Not used; Address2: Not used; Address3: Not used; Address4: Not used; DocumentNumber: 9; Revision: Not used; SheetNumber: 9; SheetTotal: 17

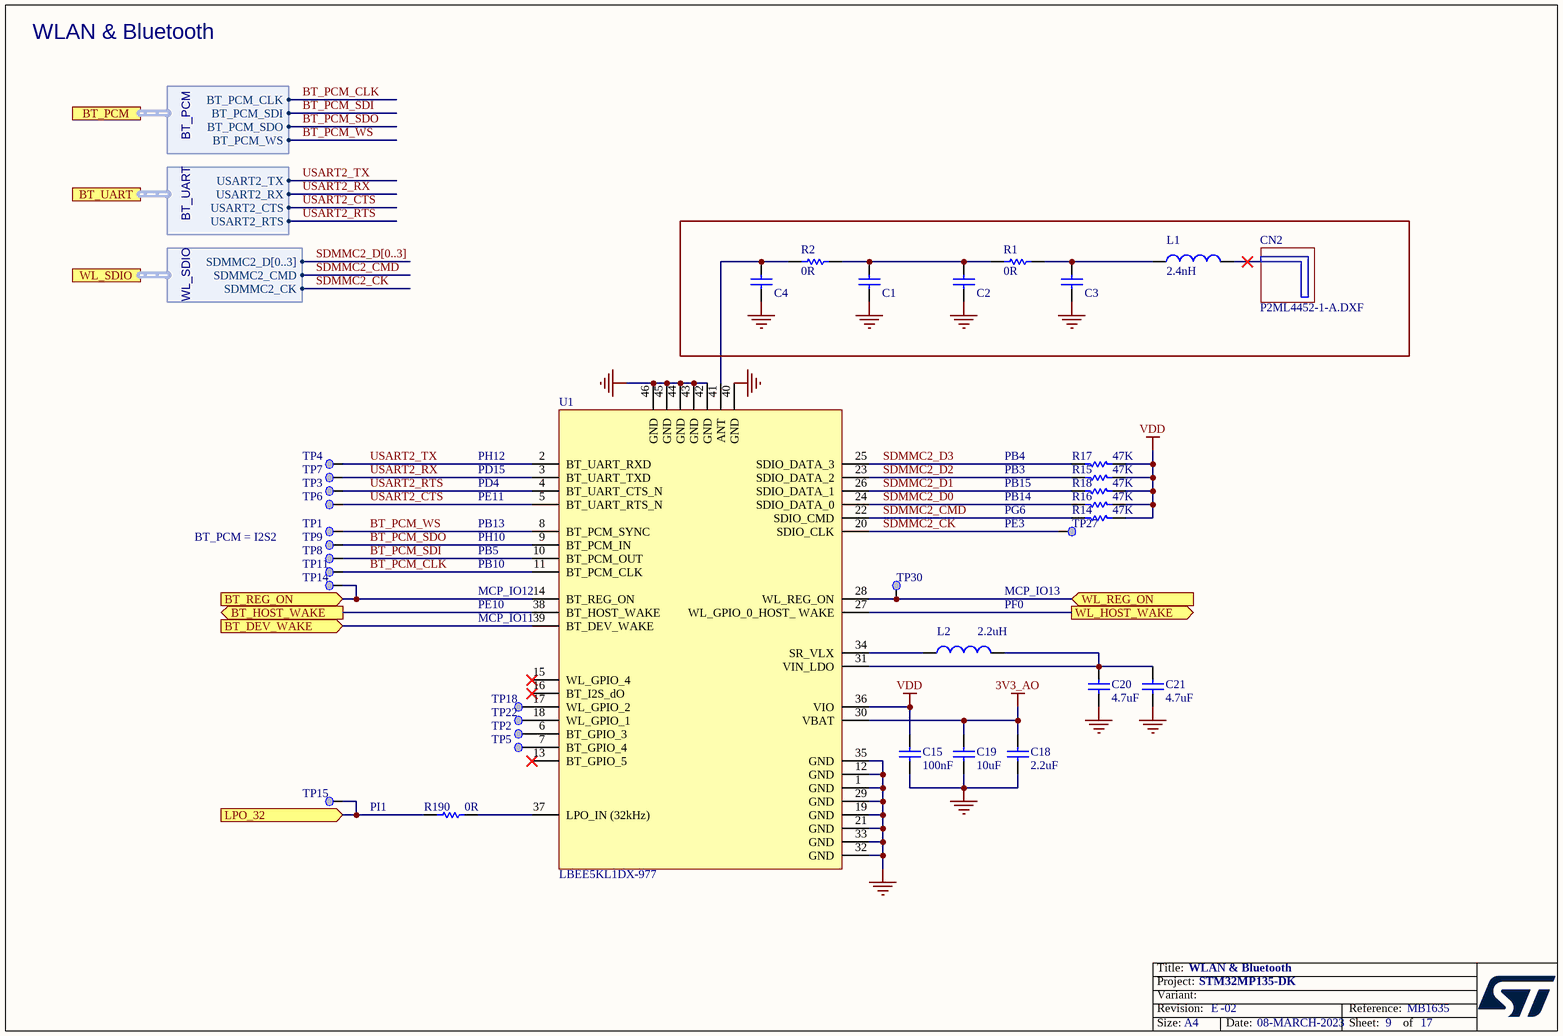
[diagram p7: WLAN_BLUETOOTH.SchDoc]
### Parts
C1  Capacitor  [C0402]  (value not drawn)
C2  Capacitor  [C0402]  (value not drawn)
C3  Capacitor  [C0402]  (value not drawn)
C4  Capacitor  [C0402]  (value not drawn)
C15  value 100nF  [C0402]  (hidden comment: Capacitor)
C18  value 2.2uF  [C0201_H0P5]  (hidden comment: Capacitor)
C19  value 10uF  [C0603]  (hidden comment: Capacitor)
C20  value 4.7uF  [C0402]  (hidden comment: Capacitor)
C21  value 4.7uF  [C0402]  (hidden comment: Capacitor)
CN2  value P2ML4452-1-A.DXF  [ANT_MURATA_TYPE-1-DX_P2ML4452-1-A_DXF]  (hidden comment: antenna_Wifi_BLE_Murata)  (no BOM)
L1  value 2.4nH  [IND_0402_MURATA_LQW15AN2N4C00X]  (hidden comment: Inductor)
L2  value 2.2uH  [L0603]  (hidden comment: Inductor)
R1  value 0R  [R0402]  (hidden comment: Resistor)
R2  value 0R  [R0402]  (hidden comment: Resistor)
R14  value 47K  [R0402]  (hidden comment: Resistor)
R15  value 47K  [R0402]  (hidden comment: Resistor)
R16  value 47K  [R0402]  (hidden comment: Resistor)
R17  value 47K  [R0402]  (hidden comment: Resistor)
R18  value 47K  [R0402]  (hidden comment: Resistor)
R190  value 0R  [R0402]  (hidden comment: Resistor)
TP1  Test Point  [TP_SMD_1MM]  (value not drawn)  (no BOM)
TP2  Test Point  [TP_SMD_1MM]  (value not drawn)  (no BOM)
TP3  Test Point  [TP_SMD_1MM]  (value not drawn)  (no BOM)
TP4  Test Point  [TP_SMD_1MM]  (value not drawn)  (no BOM)
TP5  Test Point  [TP_SMD_1MM]  (value not drawn)  (no BOM)
TP6  Test Point  [TP_SMD_1MM]  (value not drawn)  (no BOM)
TP7  Test Point  [TP_SMD_1MM]  (value not drawn)  (no BOM)
TP8  Test Point  [TP_SMD_1MM]  (value not drawn)  (no BOM)
TP9  Test Point  [TP_SMD_1MM]  (value not drawn)  (no BOM)
TP11  Test Point  [TP_SMD_1MM]  (value not drawn)  (no BOM)
TP14  Test Point  [TP_SMD_1MM]  (value not drawn)  (no BOM)
TP15  Test Point  [TP_SMD_1MM]  (value not drawn)  (no BOM)
TP18  Test Point  [TP_SMD_1MM]  (value not drawn)  (no BOM)
TP22  Test Point  [TP_SMD_1MM]  (value not drawn)  (no BOM)
TP27  Test Point  [TP_SMD_1MM]  (value not drawn)  (no BOM)
TP30  Test Point  [TP_SMD_1MM]  (value not drawn)  (no BOM)
U1  value LBEE5KL1DX-977  [MOD_WLAN-BT_MURATA_LBEE5KL1DX-883]  (hidden comment: LBEE5KL1DX-883)

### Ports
BT_DEV_WAKE (in), BT_HOST_WAKE (out), BT_PCM (harness BT_PCM), BT_REG_ON (in), BT_UART (harness BT_UART), LPO_32 (in), WL_HOST_WAKE (out), WL_REG_ON (in), WL_SDIO (harness WL_SDIO)

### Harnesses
BT_PCM: BT_PCM_CLK, BT_PCM_SDI, BT_PCM_SDO, BT_PCM_WS
BT_UART: USART2_TX, USART2_RX, USART2_CTS, USART2_RTS
WL_SDIO: SDMMC2_D[0..3], SDMMC2_CMD, SDMMC2_CK

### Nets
3V3_AO: C18.2 C19.2 U1.30(VBAT)
GND: C1.1 C2.1 C3.1 C4.1 C15.1 C18.1 C19.1 C20.1 C21.1 U1.1(GND) U1.12(GND) U1.19(GND) U1.21(GND) U1.29(GND) U1.32(GND) U1.33(GND) U1.35(GND) U1.40(GND) U1.42(GND) U1.43(GND) U1.44(GND) U1.45(GND) U1.46(GND)
VDD: C15.2 R14.1 R15.1 R16.1 R17.1 R18.1 U1.36(VIO)
BT_DEV_WAKE: U1.39(BT_DEV_WAKE) ; port BT_DEV_WAKE
BT_HOST_WAKE: U1.38(BT_HOST_WAKE) ; port BT_HOST_WAKE
BT_PCM_CLK: TP11.1 U1.11(BT_PCM_CLK) ; port BT_PCM.BT_PCM_CLK
BT_PCM_SDI: TP8.1 U1.10(BT_PCM_OUT) ; port BT_PCM.BT_PCM_SDI
BT_PCM_SDO: TP9.1 U1.9(BT_PCM_IN) ; port BT_PCM.BT_PCM_SDO
BT_PCM_WS: TP1.1 U1.8(BT_PCM_SYNC) ; port BT_PCM.BT_PCM_WS
BT_REG_ON: TP14.1 U1.14(BT_REG_ON) ; port BT_REG_ON
LPO_32: R190.1 TP15.1 ; port LPO_32
SDMMC2_CK: TP27.1 U1.20(SDIO_CLK) ; port WL_SDIO.SDMMC2_CK
SDMMC2_CMD: R14.2 U1.22(SDIO_CMD) ; port WL_SDIO.SDMMC2_CMD
SDMMC2_D0: R16.2 U1.24(SDIO_DATA_0)
SDMMC2_D1: R18.2 U1.26(SDIO_DATA_1)
SDMMC2_D2: R15.2 U1.23(SDIO_DATA_2)
SDMMC2_D3: R17.2 U1.25(SDIO_DATA_3)
USART2_CTS: TP6.1 U1.5(BT_UART_RTS_N) ; port BT_UART.USART2_CTS
USART2_RTS: TP3.1 U1.4(BT_UART_CTS_N) ; port BT_UART.USART2_RTS
USART2_RX: TP7.1 U1.3(BT_UART_TXD) ; port BT_UART.USART2_RX
USART2_TX: TP4.1 U1.2(BT_UART_RXD) ; port BT_UART.USART2_TX
WL_HOST_WAKE: U1.27(WL_GPIO_0_HOST__WAKE) ; port WL_HOST_WAKE
WL_REG_ON: TP30.1 U1.28(WL_REG_ON) ; port WL_REG_ON
NetC1_2: C1.2 C2.2 R1.2 R2.1
NetC3_2: C3.2 L1.1 R1.1
NetC4_2: C4.2 R2.2 U1.41(ANT)
NetC20_2: C20.2 C21.2 L2.2 U1.31(VIN_LDO)
NetL2_1: L2.1 U1.34(SR_VLX)
NetR190_2: R190.2 U1.37(LPO_IN_(32kHz))
NetTP2_1: TP2.1 U1.6(BT_GPIO_3)
NetTP5_1: TP5.1 U1.7(BT_GPIO_4)
NetTP18_1: TP18.1 U1.17(WL_GPIO_2)
NetTP22_1: TP22.1 U1.18(WL_GPIO_1)

Not connected (* = marked no-connect by the designer): L1 2*; U1 13(BT_GPIO_5)* 15(WL_GPIO_4)* 16(BT_I2S_dO)*

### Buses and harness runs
bus SDMMC2_D[0..3]

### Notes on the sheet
- WLAN & Bluetooth
- PD15
- PH12
- PD4
- PE11
- PG6
- PB14
- PB15
- PB3
- PB4
- BT_PCM = I2S2
- PB10
- PB5
- PH10
- PB13
- PE3
- PE10
- (near U1) MCP_IO11
- (near U1) MCP_IO12
- (near L2) PF0
- MCP_IO13
- PI1

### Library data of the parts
C1-C4 = MCD-00200: Capacitor, MLCC, 12pF, 50V, NPO, +/-5%, 0402, T=0.5mm; Manufacturer_Part_Number: CC0402JRNPO9BN120; Manufacturer: YAGEO; Part_Preference: Recommended; Component_Country_Of_Origin: China; ShowFields: YES; ID: 2667
C15 = MCD-00006: as C41 on sheet ST-Link_V3E
C18 = MCD-02235: as C60 on sheet ST-Link_V3E
C19 = MCD-00099: as C120 on sheet Power_Board
C20 C21 = MCD-01356: as C99 on sheet Power_Board
CN2 = MCD-00656: Murata_Type1DX_AntennaDesign_P2ML4452-1-A.DXF; Part_Type: Misc; Manufacturer: MURATA; Part_Preference: Recommended; Component_Country_Of_Origin: Unknown; ShowFields: YES; ID: 3086
L1 = MCD-00657: Inductor, 2.4nH, +/-0.2nH, Itemp=850mA, 50R, 0402, T=0.6mm, Qmin=20; Manufacturer_Part_Number: LQW15AN2N4C00#; Manufacturer: MURATA; Part_Preference: Recommended; Order_Code_RS: 177-6240; Component_Country_Of_Origin: Japan; ShowFields: YES; ID: 3088
L2 = MCD-00659: Inductor, 2.2uH, +/-20%, 1050mA, 0R2, 0603, T=1mm; Manufacturer_Part_Number: LQM18PN2R2MGH; Manufacturer: MURATA; Part_Preference: Recommended; Component_Country_Of_Origin: Japan; ShowFields: YES; ID: 3085
R1 R2 = MCD-00052: as R114 on sheet Power_Board
R14-R18 = MCD-00063: as R144 on sheet Power_Board
R190 = MCD-00052: as R45 on sheet ST-Link_V3E
TP1-TP9 TP11 TP14 TP15 TP18 TP22 TP27 TP30 = MCD-00074: as TP49 on sheet Power_Board
U1 = MCD-00268: IEEE802.11b/g/n W-LAN + Bluetooth 4.1+EDR module; Manufacturer: MURATA; Part_Type: IC; Part_Preference: Recommended; Component_Country_Of_Origin: Japan; ShowFields: YES; ID: 2603

## Sheet Expansion_Connector.SchDoc: Expansion connector
size A4; Project: STM32MP15-DISCO PI; Date: Not used; ApprovedBy: Not used; CheckedBy: Not used; Author: Not used; CompanyName: STMicroelectronics; DrawnBy: Not used; Engineer: Not used; Organization: Not used; Address1: Not used; Address2: Not used; Address3: Not used; Address4: Not used; DocumentNumber: 14; Revision: Not used; SheetNumber: 14; SheetTotal: 17

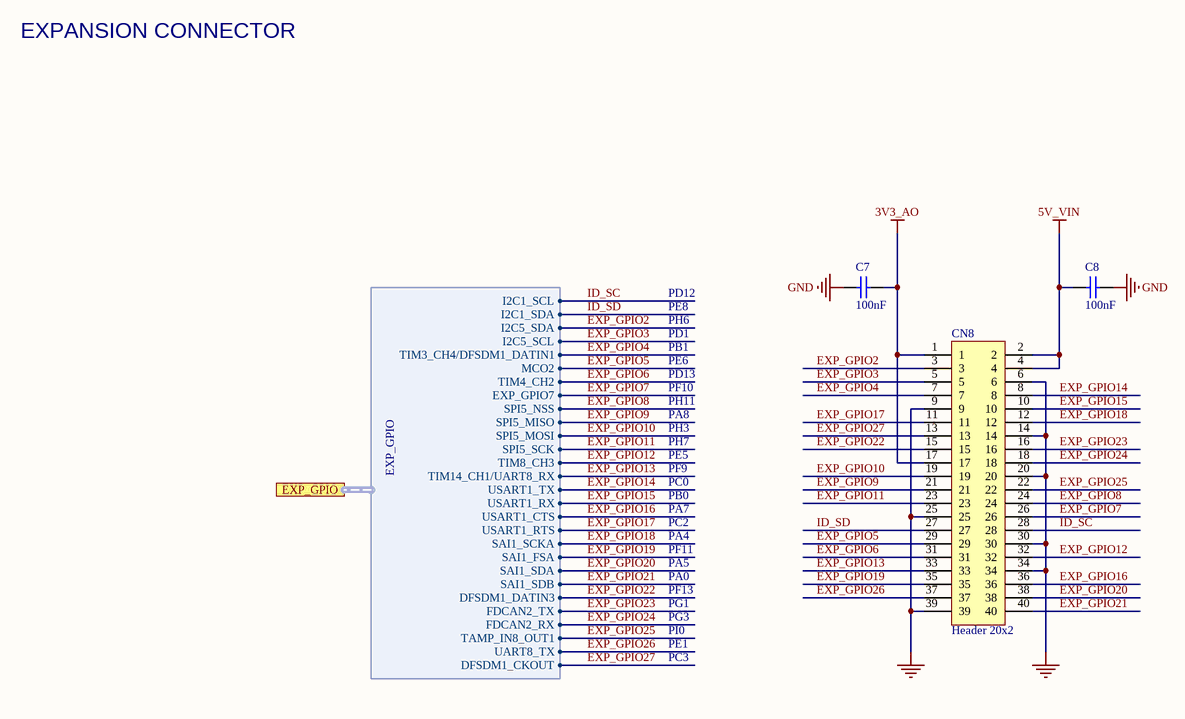
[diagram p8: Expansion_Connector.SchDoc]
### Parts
C7  value 100nF  [C0402]  (hidden comment: Capacitor)
C8  value 100nF  [C0402]  (hidden comment: Capacitor)
CN8  Header 20x2  [CON_SAMTEC_TSW-120-07-G-D]

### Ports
EXP_GPIO (harness EXP_GPIO)

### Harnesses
EXP_GPIO: I2C1_SCL, I2C1_SDA, I2C5_SDA, MCO2, TIM8_CH3, DFSDM1_DATIN3, SPI5_NSS, SPI5_MISO, SPI5_MOSI, SPI5_SCK, TIM4_CH2, USART1_TX, USART1_RX, USART1_CTS, USART1_RTS, UART8_TX, TIM14_CH1/UART8_RX, FDCAN2_TX, FDCAN2_RX, DFSDM1_CKOUT, TIM3_CH4/DFSDM1_DATIN1, I2C5_SCL, SAI1_SCKA, SAI1_FSA, SAI1_SDA, SAI1_SDB, TAMP_IN8_OUT1, EXP_GPIO7

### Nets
3V3_AO: C7.1 CN8.1 CN8.17
5V_VIN: C8.2 CN8.2 CN8.4
GND: C7.2 C8.1 CN8.6 CN8.9 CN8.14 CN8.20 CN8.25 CN8.30 CN8.34 CN8.39
EXP_GPIO2: CN8.3 ; port EXP_GPIO.I2C5_SDA
EXP_GPIO3: CN8.5 ; port EXP_GPIO.I2C5_SCL
EXP_GPIO4: CN8.7 ; port EXP_GPIO.TIM3_CH4/DFSDM1_DATIN1
EXP_GPIO5: CN8.29 ; port EXP_GPIO.MCO2
EXP_GPIO6: CN8.31 ; port EXP_GPIO.TIM4_CH2
EXP_GPIO7: CN8.26 ; port EXP_GPIO.EXP_GPIO7
EXP_GPIO8: CN8.24 ; port EXP_GPIO.SPI5_NSS
EXP_GPIO9: CN8.21 ; port EXP_GPIO.SPI5_MISO
EXP_GPIO10: CN8.19 ; port EXP_GPIO.SPI5_MOSI
EXP_GPIO11: CN8.23 ; port EXP_GPIO.SPI5_SCK
EXP_GPIO12: CN8.32 ; port EXP_GPIO.TIM8_CH3
EXP_GPIO13: CN8.33 ; port EXP_GPIO.TIM14_CH1/UART8_RX
EXP_GPIO14: CN8.8 ; port EXP_GPIO.USART1_TX
EXP_GPIO15: CN8.10 ; port EXP_GPIO.USART1_RX
EXP_GPIO16: CN8.36 ; port EXP_GPIO.USART1_CTS
EXP_GPIO17: CN8.11 ; port EXP_GPIO.USART1_RTS
EXP_GPIO18: CN8.12 ; port EXP_GPIO.SAI1_SCKA
EXP_GPIO19: CN8.35 ; port EXP_GPIO.SAI1_FSA
EXP_GPIO20: CN8.38 ; port EXP_GPIO.SAI1_SDA
EXP_GPIO21: CN8.40 ; port EXP_GPIO.SAI1_SDB
EXP_GPIO22: CN8.15 ; port EXP_GPIO.DFSDM1_DATIN3  [project net DFSDM1_DATIN3]
EXP_GPIO23: CN8.16 ; port EXP_GPIO.FDCAN2_TX
EXP_GPIO24: CN8.18 ; port EXP_GPIO.FDCAN2_RX
EXP_GPIO25: CN8.22 ; port EXP_GPIO.TAMP_IN8_OUT1
EXP_GPIO26: CN8.37 ; port EXP_GPIO.UART8_TX
EXP_GPIO27: CN8.13 ; port EXP_GPIO.DFSDM1_CKOUT  [project net DFSDM1_CKOUT]
ID_SC: CN8.28 ; port EXP_GPIO.I2C1_SCL  [project net I2C1_SCL]
ID_SD: CN8.27 ; port EXP_GPIO.I2C1_SDA  [project net I2C1_SDA]

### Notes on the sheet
- EXPANSION CONNECTOR
- PD12
- PE8
- PB1
- PD1
- PH6
- PE6
- PD13
- PF10
- PA8
- PH3
- PH7
- PH11
- PE5
- PF9
- PA7
- PC0
- PB0
- PF11
- PA4
- PA5
- PA0
- PC2
- PF13
- PG3
- PG1
- PI0
- PE1
- PC3

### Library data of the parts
C7 C8 = MCD-00006: as C65 on sheet ST-Link_V3E
CN8 = MCD-00302: Header, 20x2, 2.54mm, VR, TH, T=5.84mm/2.54mm; Manufacturer_Part_Number: TSW-120-07-G-D; Manufacturer: SAMTEC; Part_Type: Connector; Part_Preference: Recommended; Order_Code_RS: 180-2456; Component_Country_Of_Origin: China, Costa Rica, Malaysia, United States, Vietnam; ShowFields: YES; ID: 2567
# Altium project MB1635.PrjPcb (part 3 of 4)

## Sheet Peripherals.SchDoc: Peripherals
size A4; Project: STM32MP15-DISCO PI; Date: Not used; ApprovedBy: Not used; CheckedBy: Not used; Author: Not used; CompanyName: STMicroelectronics; DrawnBy: Not used; Engineer: Not used; Organization: Not used; Address1: Not used; Address2: Not used; Address3: Not used; Address4: Not used; DocumentNumber: 15; Revision: Not used; SheetNumber: 15; SheetTotal: 17

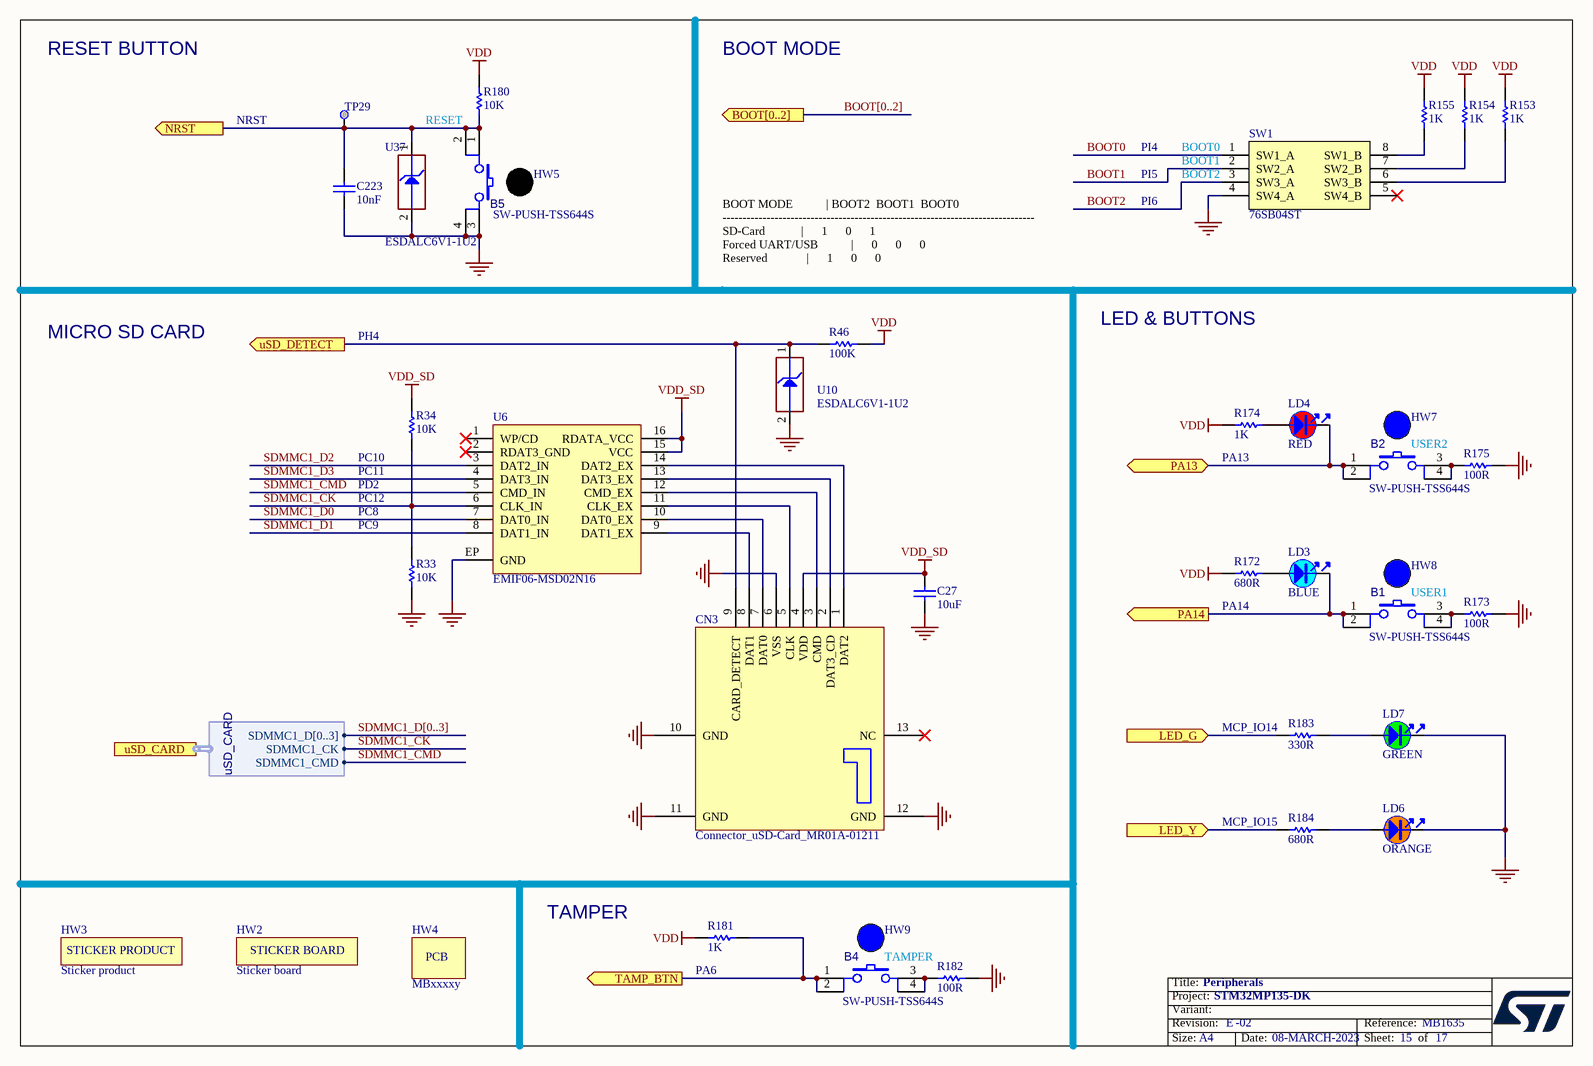
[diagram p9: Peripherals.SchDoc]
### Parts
B1  value SW-PUSH-TSS644S  [SWI_KNITTER_TSS644S]  (hidden comment: SW_PUSH_SMD)
B2  value SW-PUSH-TSS644S  [SWI_KNITTER_TSS644S]  (hidden comment: SW_PUSH_SMD)
B4  value SW-PUSH-TSS644S  [SWI_KNITTER_TSS644S]  (hidden comment: SW_PUSH_SMD)
B5  value SW-PUSH-TSS644S  [SWI_KNITTER_TSS644S]  (hidden comment: SW_PUSH_SMD)
C27  value 10uF  [C0603]  (hidden comment: Capacitor)
C223  value 10nF  [C0402]  (hidden comment: Capacitor)
CN3  value Connector_uSD-Card_MR01A-01211  [CON_MICROSD_ATOM_MR01A-01211]  (hidden comment: MR01A-01211)
HW2  value Sticker board  [STICKER_BOARD_25X9]  (hidden comment: STICKER_BOARD)  (no BOM)
HW3  value Sticker product  [STICKER_PRODUCT_25X9]  (hidden comment: STICKER_PRODUCT)  (no BOM)
HW4  value MBxxxxy  (hidden comment: PCB)  (mechanical)
HW5  SW-CAP-KTSC-62K  (value not drawn)  (mechanical)
HW7  Blue Hat  (value not drawn)  (mechanical)
HW8  Blue Hat  (value not drawn)  (mechanical)
HW9  Blue Hat  (value not drawn)  (mechanical)
LD3  value BLUE  [LED_0603_SMD-B_BLUE_H0P4]  (hidden comment: LED_blue)
LD4  value RED  [LED_0603_RED]  (hidden comment: LED_red)
LD6  value ORANGE  [LED_0603_ORANGE_H0P4]  (hidden comment: LED_orange)
LD7  value GREEN  [LED_0603_GREEN]  (hidden comment: LED_green)
R33  value 10K  [R0402]  (hidden comment: Resistor)
R34  value 10K  [R0402]  (hidden comment: Resistor)
R46  value 100K  [R0402]  (hidden comment: Resistor)
R153  value 1K  [R0402]  (hidden comment: Resistor)
R154  value 1K  [R0402]  (hidden comment: Resistor)
R155  value 1K  [R0402]  (hidden comment: Resistor)
R172  value 680R  [R0402]  (hidden comment: Resistor)
R173  value 100R  [R0402]  (hidden comment: Resistor)
R174  value 1K  [R0402]  (hidden comment: Resistor)
R175  value 100R  [R0402]  (hidden comment: Resistor)
R180  value 10K  [R0402]  (hidden comment: Resistor)
R181  value 1K  [R0402]  (hidden comment: Resistor)
R182  value 100R  [R0402]  (hidden comment: Resistor)
R183  value 330R  [R0402]  (hidden comment: Resistor)
R184  value 680R  [R0402]  (hidden comment: Resistor)
SW1  76SB04ST  [SWI_GRAYHILL-INC_76SB04ST]
TP29  Test Point  [TP_SMD_1MM]  (value not drawn)  (no BOM)
U6  EMIF06-MSD02N16  [ESD_UQFN16L-EPAD_3P5X1P2_P040]
U10  value ESDALC6V1-1U2  [ESD_ST0201]  (hidden comment: ESD-TRANSIL)
U37  value ESDALC6V1-1U2  [ESD_ST0201]  (hidden comment: ESD-TRANSIL)

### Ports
BOOT[0..2] (out), LED_G (in), LED_Y (in), NRST (out), PA13 (bidir), PA14 (out), TAMP_BTN (out), uSD_CARD (harness uSD_CARD), uSD_DETECT (out)

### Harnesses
uSD_CARD: SDMMC1_D[0..3], SDMMC1_CK, SDMMC1_CMD

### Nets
GND: B5.3 B5.4 C27.1 C223.1 CN3.6(VSS) CN3.10(GND) CN3.11(GND) CN3.12(GND) LD6.2 LD7.2 R33.1 R173.2 R175.2 R182.2 SW1.4(SW4_A) U6.EP(GND) U10.2(GND) U37.2(GND)
VDD: R46.1 R153.2 R154.2 R155.2 R172.2 R174.2 R180.2 R181.2
VDD_SD: C27.2 CN3.4(VDD) R34.2 U6.15(VCC) U6.16(RDATA_VCC)
BOOT0: SW1.1(SW1_A)
BOOT1: SW1.2(SW2_A)
BOOT2: SW1.3(SW3_A)
LED_G: R183.1 ; port LED_G
LED_Y: R184.1 ; port LED_Y
NRST: B5.1 B5.2 C223.2 R180.1 TP29.1 U37.1(IO1) ; port NRST
PA13: B2.1 B2.2 LD4.2 ; port PA13
PA14: B1.1 B1.2 LD3.2 ; port PA14
SDMMC1_CK: R33.2 R34.1 U6.6(CLK_IN) ; port uSD_CARD.SDMMC1_CK
SDMMC1_CMD: U6.5(CMD_IN) ; port uSD_CARD.SDMMC1_CMD
SDMMC1_D0: U6.7(DAT0_IN)
SDMMC1_D1: U6.8(DAT1_IN)
SDMMC1_D2: U6.3(DAT2_IN)
SDMMC1_D3: U6.4(DAT3_IN)
TAMP_BTN: B4.1 B4.2 R181.1 ; port TAMP_BTN
uSD_DETECT: CN3.9(CARD_DETECT) R46.2 U10.1(IO1) ; port uSD_DETECT
NetB1_3: B1.3 B1.4 R173.1
NetB2_3: B2.3 B2.4 R175.1
NetB4_3: B4.3 B4.4 R182.1
NetCN3_1: CN3.1(DAT2) U6.14(DAT2_EX)
NetCN3_2: CN3.2(DAT3_CD) U6.13(DAT3_EX)
NetCN3_3: CN3.3(CMD) U6.12(CMD_EX)
NetCN3_5: CN3.5(CLK) U6.11(CLK_EX)
NetCN3_7: CN3.7(DAT0) U6.10(DAT0_EX)
NetCN3_8: CN3.8(DAT1) U6.9(DAT1_EX)
NetLD3_1: LD3.1 R172.1
NetLD4_1: LD4.1 R174.1
NetLD6_1: LD6.1 R184.2
NetLD7_1: LD7.1 R183.2
NetR153_1: R153.1 SW1.6(SW3_B)
NetR154_1: R154.1 SW1.7(SW2_B)
NetR155_1: R155.1 SW1.8(SW1_B)

Not connected (* = marked no-connect by the designer): CN3 13(NC)*; SW1 5(SW4_B)*; U6 1(WP/CD)* 2(RDAT3_GND)*

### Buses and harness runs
bus BOOT[0..2] = port BOOT[0..2]
bus SDMMC1_D[0..3]

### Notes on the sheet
- RESET BUTTON
- BOOT MODE
- NRST
- RESET
- PI4
- PI5
- (near SW1) BOOT0
- (near SW1) BOOT1
- (near SW1) BOOT2
- BOOT MODE	          |	BOOT2 	BOOT1 	BOOT0
  ------------------------------------------------------------------------------
  SD-Card		          |	     1	     0	     1
  Forced UART/USB	          |	     0	     0	     0
  Reserved 		          |	     1	     0	     0
- PI6
- LED & BUTTONS
- MICRO SD CARD
- PH4
- (near R34) PC10
- (near R174) PA13
- (near B2) USER2
- (near R34) PC11
- PD2
- PC12
- PC8
- (near R33) PC9
- (near B1) USER1
- (near R172) PA14
- (near R183) MCP_IO14
- (near R184) MCP_IO15
- TAMPER
- (near R181) PA6

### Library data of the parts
B1 B2 B4 = MCD-02417: Push Button, NO, 0.05A, 12V, 2.6N, SMD, 9.0x6.2mm, T=7.3mm, changeable caps KTSC-6xx; Part_Type: Misc; Manufacturer_Part_Number: TSS644S; Manufacturer: KNITTER-SWITCH; Part_Preference: Recommended; Component_Country_Of_Origin: China; ShowFields: YES; ID: 4523
B5 = MCD-02417: Push Button, NO, 0.05A, 12V, 2.6N, SMD, 9.0x6.2mm, T=7.3mm, changeable caps KTSC-6xx; Manufacturer_Part_Number: TSS644S; Manufacturer: KNITTER-SWITCH; Part_Type: Misc; Part_Preference: Recommended; Component_Country_Of_Origin: China; ShowFields: YES; ID: 4523
C27 = MCD-00099: Capacitor, MLCC, 10uF, 10V, X5R, +/-10%, 0603, T=0.8mm; Manufacturer_Part_Number: GRM188R61A106KE69D; Manufacturer: MURATA; Part_Preference: Recommended; Order_Code_RS: 170-6168; Component_Country_Of_Origin: Japan; ShowFields: YES; ID: 2770
C223 = MCD-02198: Capacitor, MLCC, 10nF, 50V, X7R, +/-10%, 0402, T=0.5mm; Manufacturer_Part_Number: CC0402KRX7R9BB103; Manufacturer: YAGEO; Part_Preference: Recommended; Order_Code_RS: 6169644; Component_Country_Of_Origin: China; ShowFields: YES; ID: 4298
CN3 = MCD-00653: Connector_uSD Card, Top Mnt Push-Push; Manufacturer: ATOM; Part_Preference: Recommended; Component_Country_Of_Origin: Unknown; ShowFields: YES; ID: 3087
HW2 = MCD-00235: Sticker Board 25x9 mm; Part_Type: Misc; Part_Preference: Recommended; ShowFields: YES; ID: 2632
HW3 = MCD-00547: Sticker product 25x9 mm; Part_Type: Misc; Part_Preference: Recommended; ShowFields: YES; ID: 3197
HW4 = MCD-00216: PCB, xxxx for PCB number, Y for PCB revision; Part_Type: Misc; Part_Preference: Forbidden; ShowFields: YES; ID: 2653
HW5 = MCD-02420: Black round cap for TSS6x series; Part_Type: Mechanical; Part_Preference: Recommended; Manufacturer: KNITTER-SWITCH; Component_Country_Of_Origin: China; ShowFields: YES; ID: 4526
HW7-HW9 = MCD-02136: Switch hat, blue, For KTSC-62B; Part_Type: Misc; Part_Preference: Recommended; Manufacturer: APEM INC; Manufacturer_Part_Number: AKTSC62B; Order_Code_RS: 378-6779; Component_Country_Of_Origin: Unknown; ShowFields: YES; ID: 4236
LD3 = MCD-01131: LED Blue, 0603 SMD, Forward Voltage Min=2,8V, Max=3,1V; Part_Type: Display; Manufacturer_Part_Number: 19-217-BHC-ZL1M2RY-3T; Manufacturer: EVERLIGHT; Part_Preference: Forbidden; Component_Country_Of_Origin: China; ShowFields: YES; ID: 3365
LD4 = MCD-00049: LED, Red, 0603; Manufacturer_Part_Number: 19-213-R6C-AP1Q2B/3T; Manufacturer: EVERLIGHT; Part_Type: Display; Part_Preference: Forbidden; Component_Country_Of_Origin: China; ShowFields: YES; ID: 2543
LD6 = MCD-00321: LED, Orange, 0603; Part_Type: Display; Manufacturer_Part_Number: 19-217/S2C-AM2N2VY/3T; Manufacturer: EVERLIGHT; Part_Preference: Forbidden; Component_Country_Of_Origin: China; ShowFields: YES; ID: 2957
LD7 = MCD-00050: LED, Green, 0603; Manufacturer_Part_Number: 19-213SYGC/S530-E2/TR8; Manufacturer: EVERLIGHT; Part_Type: Display; Part_Preference: Forbidden; Component_Country_Of_Origin: China; ShowFields: YES; ID: 2542
R33 R34 R180 = MCD-00053: Resistor, 10K, 0402, +/-1%, 1/16W; Manufacturer_Part_Number: RC0402FR-0710KL; Manufacturer: YAGEO; BMS_Part_Number: 9131590; Part_Preference: Recommended; Component_Country_Of_Origin: China; ShowFields: YES; ID: 2539
R46 = MCD-00059: Resistor, 100K, 0402, +/-1%, 1/16W; Part_Preference: Recommended; Manufacturer: YAGEO; Manufacturer_Part_Number: RC0402FR-07100KL; Component_Country_Of_Origin: China; ShowFields: YES; ID: 2533
R153-R155 R174 R181 = MCD-00061: Resistor, 1K, 0402, +/-1%,1/16W; Manufacturer_Part_Number: RC0402FR-071KL; Manufacturer: YAGEO; Part_Preference: Recommended; Component_Country_Of_Origin: China; ShowFields: YES; ID: 2532
R172 R184 = MCD-00507: Resistor, 680R, 0402, +/-1%, 1/16W; Manufacturer_Part_Number: RC0402FR-07680RL; Manufacturer: YAGEO; Part_Preference: Recommended; Component_Country_Of_Origin: China; ShowFields: YES; ID: 3238
R173 R175 R182 = MCD-00067: Resistor, 100R, 0402, +/- 1%, 1/16W; Manufacturer_Part_Number: RC0402FR-07100RL; Manufacturer: YAGEO; Part_Preference: Recommended; Component_Country_Of_Origin: China; ShowFields: YES; ID: 2527
R183 = MCD-00062: Resistor, 330R, 0402, +/-1%, 1/16W; Manufacturer_Part_Number: RC0402FR-07330RL; Manufacturer: YAGEO; Part_Preference: Recommended; Component_Country_Of_Origin: China; ShowFields: YES; ID: 2529
SW1 = MCD-02256: Quad SPST switch, TH, 2.54mm pitch, height 7.5mm; Part_Preference: Recommended; Part_Type: Misc; Manufacturer: GRAYHILL; Order_Code_RS: 878-0230; Component_Country_Of_Origin: China; ShowFields: YES; ID: 4356
TP29 = MCD-00074: Test Point 1mm; Part_Type: Misc; Part_Preference: Recommended; ShowFields: YES; ID: 2518
U6 = MCD-00249: ESD protection for SD card 2.0; BMS_Part_Number: 9179003; Part_Preference: Recommended; Part_Type: Diode; Manufacturer: STMICROELECTRONICS; Manufacturer_HQ_COO: EU; Order_Code_RS: 165-8188; Component_Country_Of_Origin: Thailand; ShowFields: YES; ID: 2617
U10 U37 = MCD-00170: ESD protection 6V1; Part_Type: Diode; Manufacturer: STMICROELECTRONICS; BMS_Part_Number: 9151132; Part_Preference: Recommended; Manufacturer_HQ_COO: EU; Component_Country_Of_Origin: China; ShowFields: YES; ID: 2696

## Sheet MP135_11x11.SchDoc: STM32 MPU I/Os
size A3; Date: Not used; ApprovedBy: Not used; CheckedBy: Not used; Author: Not used; CompanyName: STMicroelectronics; DrawnBy: Not used; Engineer: Not used; Organization: Not used; Address1: Not used; Address2: Not used; Address3: Not used; Address4: Not used; DocumentNumber: 3; Revision: Not used; SheetNumber: 3; SheetTotal: 17

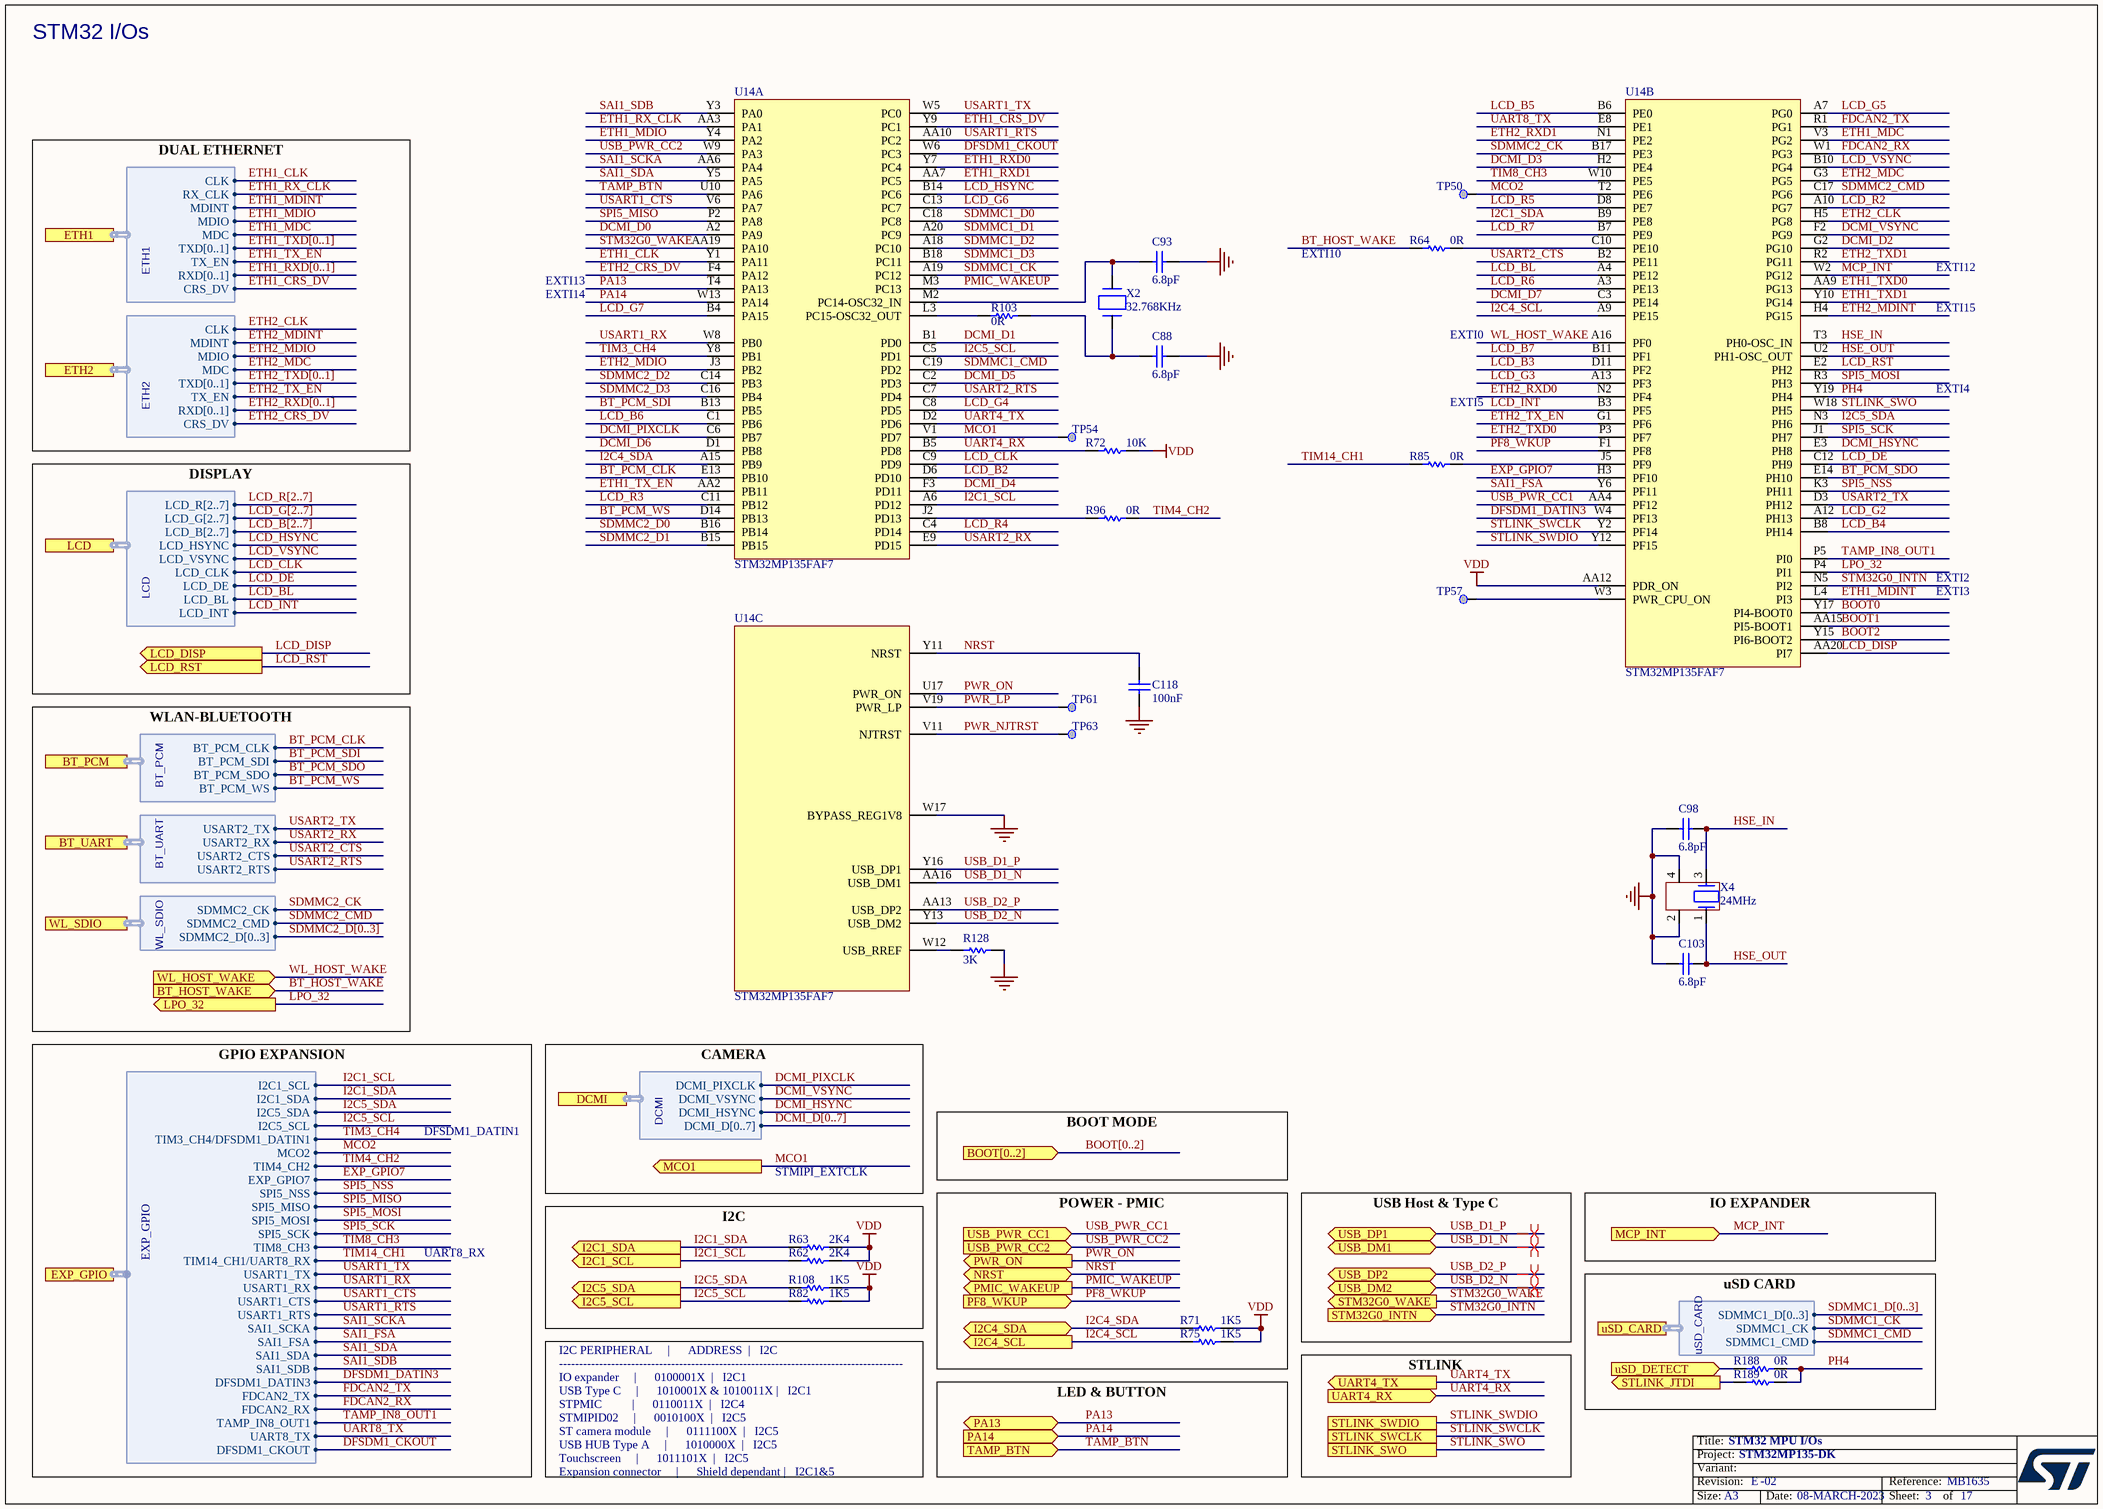
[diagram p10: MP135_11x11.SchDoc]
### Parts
C88  value 6.8pF  [C0402]  (hidden comment: Capacitor)
C93  value 6.8pF  [C0402]  (hidden comment: Capacitor)
C98  value 6.8pF  [C0402]  (hidden comment: Capacitor)
C103  value 6.8pF  [C0402]  (hidden comment: Capacitor)
C118  value 100nF  [C0402]  (hidden comment: Capacitor)
R62  value 2K4  [R0402]  (hidden comment: Resistor)
R63  value 2K4  [R0402]  (hidden comment: Resistor)
R64  value 0R  [R0402]  (hidden comment: Resistor)
R71  value 1K5  [R0402]  (hidden comment: Resistor)
R72  value 10K  [R0402]  (hidden comment: Resistor)
R75  value 1K5  [R0402]  (hidden comment: Resistor)
R82  value 1K5  [R0402]  (hidden comment: Resistor)
R85  value 0R  [R0402]  (hidden comment: Resistor)
R96  value 0R  [R0402]  (hidden comment: Resistor)
R103  value 0R  [R0402]  (hidden comment: Resistor)
R108  value 1K5  [R0402]  (hidden comment: Resistor)
R128  value 3K  [R0402]  (hidden comment: Resistor)
R188  value 0R  [R0402]  (hidden comment: Resistor)
R189  value 0R  [R0402]  (hidden comment: Resistor)
TP50  Test Point  [TP_SMD_1MM]  (value not drawn)  (no BOM)
TP54  Test Point  [TP_SMD_1MM]  (value not drawn)  (no BOM)
TP57  Test Point  [TP_SMD_1MM]  (value not drawn)  (no BOM)
TP61  Test Point  [TP_SMD_1MM]  (value not drawn)  (no BOM)
TP63  Test Point  [TP_SMD_1MM]  (value not drawn)  (no BOM)
U14  STM32MP135FAF7  [ICC_TFBGA320_11X11_STM32MP135FA7_P050_H1P20]  (parts A,B,C of 5)
X2  value 32.768KHz  [CRY_NX2012SA_2P]  (hidden comment: XTAL_2_PINS)
X4  value 24MHz  [CRY_NX2016SA_4P]  (hidden comment: XTAL_4_PINS)

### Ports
BOOT[0..2] (in), BT_HOST_WAKE (in), BT_PCM (harness BT_PCM), BT_UART (harness BT_UART), DCMI (harness DCMI), ETH1 (harness ETH1), ETH2 (harness ETH2), EXP_GPIO (harness EXP_GPIO), I2C1_SCL (out), I2C1_SDA (out), I2C4_SCL (out), I2C4_SDA (bidir), I2C5_SCL (out), I2C5_SDA (out), LCD (harness LCD), LCD_DISP (out), LCD_RST (out), LPO_32 (out), MCO1 (out), MCP_INT (in), NRST (bidir), PA13 (bidir), PA14 (in), PF8_WKUP (in), PMIC_WAKEUP (out), PWR_ON (out), STLINK_JTDI (out), STLINK_SWCLK, STLINK_SWDIO, STLINK_SWO, STM32G0_INTN (in), STM32G0_WAKE (out), TAMP_BTN (in), UART4_RX (in), UART4_TX (out), USB_DM1 (bidir), USB_DM2 (bidir), USB_DP1 (bidir), USB_DP2 (bidir), USB_PWR_CC1 (in), USB_PWR_CC2 (in), uSD_CARD (harness uSD_CARD), uSD_DETECT (in), WL_HOST_WAKE (in), WL_SDIO (harness WL_SDIO)

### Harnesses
BT_PCM: BT_PCM_CLK, BT_PCM_SDI, BT_PCM_SDO, BT_PCM_WS
BT_UART: USART2_TX, USART2_RX, USART2_CTS, USART2_RTS
WL_SDIO: SDMMC2_CMD, SDMMC2_CK, SDMMC2_D[0..3]
LCD: LCD_R[2..7], LCD_G[2..7], LCD_B[2..7], LCD_HSYNC, LCD_VSYNC, LCD_DE, LCD_CLK, LCD_BL, LCD_INT
DCMI: DCMI_D[0..7], DCMI_HSYNC, DCMI_VSYNC, DCMI_PIXCLK
ETH2: MDINT, TXD[0..1], MDIO, MDC, TX_EN, RXD[0..1], CRS_DV, CLK
ETH1: MDINT, TXD[0..1], MDIO, MDC, RX_CLK, TX_EN, RXD[0..1], CRS_DV, CLK
uSD_CARD: SDMMC1_D[0..3], SDMMC1_CK, SDMMC1_CMD
EXP_GPIO: I2C1_SCL, I2C1_SDA, I2C5_SDA, MCO2, TIM8_CH3, DFSDM1_DATIN3, SPI5_NSS, SPI5_MISO, SPI5_MOSI, SPI5_SCK, TIM4_CH2, USART1_TX, USART1_RX, USART1_CTS, USART1_RTS, UART8_TX, TIM14_CH1/UART8_RX, FDCAN2_TX, FDCAN2_RX, DFSDM1_CKOUT, TIM3_CH4/DFSDM1_DATIN1, I2C5_SCL, SAI1_SCKA, SAI1_FSA, SAI1_SDA, SAI1_SDB, TAMP_IN8_OUT1, EXP_GPIO7

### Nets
GND: C88.2 C93.2 C98.1 C103.2 C118.2 R128.2 U14.W17(BYPASS_REG1V8) X4.2 X4.4
VDD: R62.2 R63.2 R71.2 R72.2 R75.2 R82.2 R108.2 U14.AA12(PDR_ON)
BOOT0: U14.Y17(PI4-BOOT0)
BOOT1: U14.AA15(PI5-BOOT1)
BOOT2: U14.Y15(PI6-BOOT2)
BT_HOST_WAKE: R64.1 ; port BT_HOST_WAKE
BT_PCM_CLK: U14.E13(PB10) ; port BT_PCM.BT_PCM_CLK
BT_PCM_SDI: U14.B13(PB5) ; port BT_PCM.BT_PCM_SDI
BT_PCM_SDO: U14.E14(PH10) ; port BT_PCM.BT_PCM_SDO
BT_PCM_WS: U14.D14(PB13) ; port BT_PCM.BT_PCM_WS
DCMI_D0: U14.A2(PA9)
DCMI_D1: U14.B1(PD0)
DCMI_D2: U14.G2(PG10)
DCMI_D3: U14.H2(PE4)
DCMI_D4: U14.F3(PD11)
DCMI_D5: U14.C2(PD3)
DCMI_D6: U14.D1(PB8)
DCMI_D7: U14.C3(PE14)
DCMI_HSYNC: U14.E3(PH8) ; port DCMI.DCMI_HSYNC
DCMI_PIXCLK: U14.C6(PB7) ; port DCMI.DCMI_PIXCLK
DCMI_VSYNC: U14.F2(PG9) ; port DCMI.DCMI_VSYNC
DFSDM1_CKOUT: U14.W6(PC3) ; port EXP_GPIO.DFSDM1_CKOUT
DFSDM1_DATIN3: U14.W4(PF13) ; port EXP_GPIO.DFSDM1_DATIN3
ETH1_CLK: U14.Y1(PA11) ; port ETH1.CLK
ETH1_CRS_DV: U14.Y9(PC1) ; port ETH1.CRS_DV
ETH1_MDC: U14.V3(PG2) ; port ETH1.MDC
ETH1_MDINT: U14.L4(PI3) ; port ETH1.MDINT
ETH1_MDIO: U14.Y4(PA2) ; port ETH1.MDIO
ETH1_RX_CLK: U14.AA3(PA1) ; port ETH1.RX_CLK
ETH1_RXD0: U14.Y7(PC4)
ETH1_RXD1: U14.AA7(PC5)
ETH1_TX_EN: U14.AA2(PB11) ; port ETH1.TX_EN
ETH1_TXD0: U14.AA9(PG13)
ETH1_TXD1: U14.Y10(PG14)
ETH2_CLK: U14.H5(PG8) ; port ETH2.CLK
ETH2_CRS_DV: U14.F4(PA12) ; port ETH2.CRS_DV
ETH2_MDC: U14.G3(PG5) ; port ETH2.MDC
ETH2_MDINT: U14.H4(PG15) ; port ETH2.MDINT
ETH2_MDIO: U14.J3(PB2) ; port ETH2.MDIO
ETH2_RXD0: U14.N2(PF4)
ETH2_RXD1: U14.N1(PE2)
ETH2_TX_EN: U14.G1(PF6) ; port ETH2.TX_EN
ETH2_TXD0: U14.P3(PF7)
ETH2_TXD1: U14.R2(PG11)
EXP_GPIO7: U14.H3(PF10) ; port EXP_GPIO.EXP_GPIO7
FDCAN2_RX: U14.W1(PG3) ; port EXP_GPIO.FDCAN2_RX  [project net EXP_GPIO24]
FDCAN2_TX: U14.R1(PG1) ; port EXP_GPIO.FDCAN2_TX  [project net EXP_GPIO23]
HSE_IN: C98.2 U14.T3(PH0-OSC_IN) X4.3
HSE_OUT: C103.1 U14.U2(PH1-OSC_OUT) X4.1
I2C1_SCL: R62.1 U14.A6(PD12) ; port I2C1_SCL, port EXP_GPIO.I2C1_SCL
I2C1_SDA: R63.1 U14.B9(PE8) ; port I2C1_SDA, port EXP_GPIO.I2C1_SDA
I2C4_SCL: R75.1 U14.A9(PE15) ; port I2C4_SCL
I2C4_SDA: R71.1 U14.A15(PB9) ; port I2C4_SDA
I2C5_SCL: R82.1 U14.C5(PD1) ; port I2C5_SCL, port EXP_GPIO.I2C5_SCL  [project net EXP_GPIO3]
I2C5_SDA: R108.1 U14.N3(PH6) ; port I2C5_SDA, port EXP_GPIO.I2C5_SDA  [project net EXP_GPIO2]
LCD_B2: U14.D6(PD10)
LCD_B3: U14.D11(PF2)
LCD_B4: U14.B8(PH14)
LCD_B5: U14.B6(PE0)
LCD_B6: U14.C1(PB6)
LCD_B7: U14.B11(PF1)
LCD_BL: U14.A4(PE12) ; port LCD.LCD_BL
LCD_CLK: U14.C9(PD9) ; port LCD.LCD_CLK
LCD_DE: U14.C12(PH9) ; port LCD.LCD_DE
LCD_DISP: U14.AA20(PI7) ; port LCD_DISP
LCD_G2: U14.A12(PH13)
LCD_G3: U14.A13(PF3)
LCD_G4: U14.C8(PD5)
LCD_G5: U14.A7(PG0)
LCD_G6: U14.C13(PC7)
LCD_G7: U14.B4(PA15)
LCD_HSYNC: U14.B14(PC6) ; port LCD.LCD_HSYNC
LCD_INT: U14.B3(PF5) ; port LCD.LCD_INT
LCD_R2: U14.A10(PG7)
LCD_R3: U14.C11(PB12)
LCD_R4: U14.C4(PD14)
LCD_R5: U14.D8(PE7)
LCD_R6: U14.A3(PE13)
LCD_R7: U14.B7(PE9)
LCD_RST: U14.E2(PH2) ; port LCD_RST
LCD_VSYNC: U14.B10(PG4) ; port LCD.LCD_VSYNC
LPO_32: U14.P4(PI1) ; port LPO_32
MCO1: TP54.1 U14.V1(PD7) ; port MCO1
MCO2: TP50.1 U14.T2(PE6) ; port EXP_GPIO.MCO2  [project net EXP_GPIO5]
MCP_INT: U14.W2(PG12) ; port MCP_INT
NRST: C118.1 U14.Y11(NRST) ; port NRST
PA13: U14.T4(PA13) ; port PA13
PA14: U14.W13(PA14) ; port PA14
PF8_WKUP: U14.F1(PF8) ; port PF8_WKUP
PH4: R188.2 R189.2 U14.Y19(PH4)
PMIC_WAKEUP: U14.M3(PC13) ; port PMIC_WAKEUP
PWR_LP: TP61.1 U14.V19(PWR_LP)
PWR_NJTRST: TP63.1 U14.V11(NJTRST)
PWR_ON: U14.U17(PWR_ON) ; port PWR_ON
SAI1_FSA: U14.Y6(PF11) ; port EXP_GPIO.SAI1_FSA  [project net EXP_GPIO19]
SAI1_SCKA: U14.AA6(PA4) ; port EXP_GPIO.SAI1_SCKA  [project net EXP_GPIO18]
SAI1_SDA: U14.Y5(PA5) ; port EXP_GPIO.SAI1_SDA  [project net EXP_GPIO20]
SAI1_SDB: U14.Y3(PA0) ; port EXP_GPIO.SAI1_SDB  [project net EXP_GPIO21]
SDMMC1_CK: U14.A19(PC12) ; port uSD_CARD.SDMMC1_CK
SDMMC1_CMD: U14.C19(PD2) ; port uSD_CARD.SDMMC1_CMD
SDMMC1_D0: U14.C18(PC8)
SDMMC1_D1: U14.A20(PC9)
SDMMC1_D2: U14.A18(PC10)
SDMMC1_D3: U14.B18(PC11)
SDMMC2_CK: U14.B17(PE3) ; port WL_SDIO.SDMMC2_CK
SDMMC2_CMD: U14.C17(PG6) ; port WL_SDIO.SDMMC2_CMD
SDMMC2_D0: U14.B16(PB14)
SDMMC2_D1: U14.B15(PB15)
SDMMC2_D2: U14.C14(PB3)
SDMMC2_D3: U14.C16(PB4)
SPI5_MISO: U14.P2(PA8) ; port EXP_GPIO.SPI5_MISO  [project net EXP_GPIO9]
SPI5_MOSI: U14.R3(PH3) ; port EXP_GPIO.SPI5_MOSI  [project net EXP_GPIO10]
SPI5_NSS: U14.K3(PH11) ; port EXP_GPIO.SPI5_NSS  [project net EXP_GPIO8]
SPI5_SCK: U14.J1(PH7) ; port EXP_GPIO.SPI5_SCK  [project net EXP_GPIO11]
STLINK_SWCLK: U14.Y2(PF14) ; port STLINK_SWCLK
STLINK_SWDIO: U14.Y12(PF15) ; port STLINK_SWDIO
STLINK_SWO: U14.W18(PH5) ; port STLINK_SWO
STM32G0_INTN: U14.N5(PI2) ; port STM32G0_INTN
STM32G0_WAKE: U14.AA19(PA10) ; port STM32G0_WAKE
T_JTDI: R189.1 ; port STLINK_JTDI
TAMP_BTN: U14.U10(PA6) ; port TAMP_BTN
TAMP_IN8_OUT1: U14.P5(PI0) ; port EXP_GPIO.TAMP_IN8_OUT1  [project net EXP_GPIO25]
TIM3_CH4: U14.Y8(PB1) ; port EXP_GPIO.TIM3_CH4/DFSDM1_DATIN1  [project net EXP_GPIO4]
TIM4_CH2: R96.2 ; port EXP_GPIO.TIM4_CH2  [project net EXP_GPIO6]
TIM8_CH3: U14.W10(PE5) ; port EXP_GPIO.TIM8_CH3  [project net EXP_GPIO12]
TIM14_CH1: R85.1 ; port EXP_GPIO.TIM14_CH1/UART8_RX  [project net EXP_GPIO13]
UART4_RX: R72.1 U14.B5(PD8) ; port UART4_RX
UART4_TX: U14.D2(PD6) ; port UART4_TX
UART8_TX: U14.E8(PE1) ; port EXP_GPIO.UART8_TX  [project net EXP_GPIO26]
USART1_CTS: U14.V6(PA7) ; port EXP_GPIO.USART1_CTS  [project net EXP_GPIO16]
USART1_RTS: U14.AA10(PC2) ; port EXP_GPIO.USART1_RTS  [project net EXP_GPIO17]
USART1_RX: U14.W8(PB0) ; port EXP_GPIO.USART1_RX  [project net EXP_GPIO15]
USART1_TX: U14.W5(PC0) ; port EXP_GPIO.USART1_TX  [project net EXP_GPIO14]
USART2_CTS: U14.B2(PE11) ; port BT_UART.USART2_CTS
USART2_RTS: U14.C7(PD4) ; port BT_UART.USART2_RTS
USART2_RX: U14.E9(PD15) ; port BT_UART.USART2_RX
USART2_TX: U14.D3(PH12) ; port BT_UART.USART2_TX
USB_D1_N: U14.AA16(USB_DM1) ; port USB_DM1
USB_D1_P: U14.Y16(USB_DP1) ; port USB_DP1
USB_D2_N: U14.Y13(USB_DM2) ; port USB_DM2
USB_D2_P: U14.AA13(USB_DP2) ; port USB_DP2
USB_PWR_CC1: U14.AA4(PF12) ; port USB_PWR_CC1
USB_PWR_CC2: U14.W9(PA3) ; port USB_PWR_CC2
uSD_DETECT: R188.1 ; port uSD_DETECT
WL_HOST_WAKE: U14.A16(PF0) ; port WL_HOST_WAKE
NetC88_1: C88.1 R103.2 X2.1(X1)
NetC93_1: C93.1 U14.M2(PC14-OSC32_IN) X2.2(X2)
NetR64_2: R64.2 U14.C10(PE10)
NetR85_2: R85.2 U14.J5(PF9)
NetR96_1: R96.1 U14.J2(PD13)
NetR103_1: R103.1 U14.L3(PC15-OSC32_OUT)
NetR128_1: R128.1 U14.W12(USB_RREF)
NetTP57_1: TP57.1 U14.W3(PWR_CPU_ON)

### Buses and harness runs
bus BOOT[0..2] = port BOOT[0..2]
bus DCMI_D[0..7]
bus ETH1_RXD[0..1]
bus ETH1_TXD[0..1]
bus ETH2_RXD[0..1]
bus ETH2_TXD[0..1]
bus LCD_B[2..7]
bus LCD_G[2..7]
bus LCD_R[2..7]
bus SDMMC1_D[0..3]
bus SDMMC2_D[0..3]

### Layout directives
differential pair: USB_D1_N, USB_D1_P, USB_D2_N, USB_D2_P

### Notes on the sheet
- STM32 I/Os
- EXTI14
- EXTI13
- EXTI10
- EXTI12
- EXTI15
- EXTI0
- DUAL ETHERNET
- EXTI5
- EXTI4
- EXTI2
- EXTI3
- DISPLAY
- WLAN-BLUETOOTH
- DFSDM1_DATIN1
- CAMERA
- STMIPI_EXTCLK
- BOOT MODE
- UART8_RX
- IO EXPANDER
- I2C
- POWER - PMIC
- USB Host & Type C
- uSD CARD
- GPIO EXPANSION
- I2C PERIPHERAL	    |      ADDRESS		|   I2C
  --------------------------------------------------------------------------------------
  IO expander	    |      0100001X		|   I2C1
  USB Type C	    |      1010001X & 1010011X	|   I2C1
  STPMIC	    	    |      0110011X		|   I2C4
  STMIPID02	    |      0010100X		|   I2C5
  ST camera module	    |      0111100X		|   I2C5
  USB HUB Type A	    |      1010000X		|   I2C5
  Touchscreen	    |      1011101X		|   I2C5
  Expansion connector	    |      Shield dependant	|   I2C1&5
- LED & BUTTON
- STLINK

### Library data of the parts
C88 C93 C98 C103 = MCD-00674: Capacitor, MLCC, 6.8pF, 50V, NPO, +/-0.25pF, 0402, T=0.5mm; Manufacturer_Part_Number: CC0402CRNPO9BN6R8; Manufacturer: YAGEO; Part_Preference: Recommended; Component_Country_Of_Origin: China; ShowFields: YES; ID: 3068
C118 = MCD-00006: Capacitor, MLCC, 100nF, 16V, X7R, +/-10%, 0402, T=0.5mm; Manufacturer_Part_Number: CC0402KRX7R7BB104; Manufacturer: YAGEO; Part_Preference: Recommended; Order_Code_RS: 616-9701; Component_Country_Of_Origin: China; ShowFields: YES; ID: 2474
R62 R63 = MCD-00433: Resistor, 2K4, 0402, +/-1%, 1/16W; Part_Preference: Recommended; Manufacturer: YAGEO; Manufacturer_Part_Number: RC0402FR-072K4L; Component_Country_Of_Origin: China; ShowFields: YES; ID: 2843
R64 R85 R96 R188 R189 = MCD-00052: Resistor, 0R, 0402, +/-5%, 1/16W; Part_Preference: Recommended; Manufacturer: YAGEO; Manufacturer_Part_Number: RC0402JR-070RL; Order_Code_RS: 618-5804; Component_Country_Of_Origin: China; ShowFields: YES; ID: 2540
R71 R75 R82 R108 = MCD-00068: Resistor, 1K5, 0402, +/-1%, 1/16W; Part_Preference: Recommended; Manufacturer: YAGEO; Manufacturer_Part_Number: RC0402FR-071K5L; Component_Country_Of_Origin: China; ShowFields: YES; ID: 2524
R72 = MCD-00053: as R33 on sheet Peripherals
R103 = MCD-00052: Resistor, 0R, 0402, +/-5%, 1/16W; Manufacturer_Part_Number: RC0402JR-070RL; Manufacturer: YAGEO; Part_Preference: Recommended; Order_Code_RS: 618-5804; Component_Country_Of_Origin: China; ShowFields: YES; ID: 2540
R128 = MCD-00185: Resistor, 3K, 0402, +/-1%, 1/16W; Part_Preference: Recommended; Manufacturer: YAGEO; Manufacturer_Part_Number: RC0402FR-073KL; Component_Country_Of_Origin: China; ShowFields: YES; ID: 2682
TP50 TP54 TP57 TP61 TP63 = MCD-00074: as TP29 on sheet Peripherals
U14 = MCD-02251: Cortex-A7 @ 900MHz, 128KB-ROM, 128KB-SRAM, 2x Ethernet, 2x ADC, 2x CAN FD, TSC, Camera, Display, Secure Boot, Cryptography, DRAM enc/dec, PKA; Part_Preference: Recommended; Part_Type: IC; Manufacturer: STMICROELECTRONICS; Manufacturer_HQ_COO: EU; Component_Country_Of_Origin: Unknown; ShowFields: YES; ID: 4351
X2 = MCD-01479: Crystal, 32.768kHz, 6pF, +/-20ppm, 80K, 2.05x1.2mm; Part_Type: Crystal_Osc; Manufacturer_Part_Number: NX2012SA-32.768KHZ-EXS00A-MU00527; Manufacturer: NDK; BMS_Part_Number: 9157049; Part_Preference: Recommended; Component_Country_Of_Origin: Unknown; ShowFields: YES; ID: 3579
X4 = MCD-01036: Crystal, 24MHz, 6pF, +/-20ppm, 80R, 2x1.6mm; BMS_Part_Number: 9157045; Part_Type: Crystal_Osc; Part_Preference: Recommended; Manufacturer: NDK; Manufacturer_Part_Number: NX2016SA-24MHZ-EXS00A-CS10820; Component_Country_Of_Origin: Unknown; ShowFields: YES; ID: 2989

## Sheet LCD4.3.SchDoc: LCD 4.3"
size A4; Date: Not used; ApprovedBy: Not used; CheckedBy: Not used; Author: Not used; CompanyName: STMicroelectronics; DrawnBy: Not used; Engineer: Not used; Organization: Not used; Address1: Not used; Address2: Not used; Address3: Not used; Address4: Not used; DocumentNumber: 10; Revision: Not used; SheetNumber: 10; SheetTotal: 17

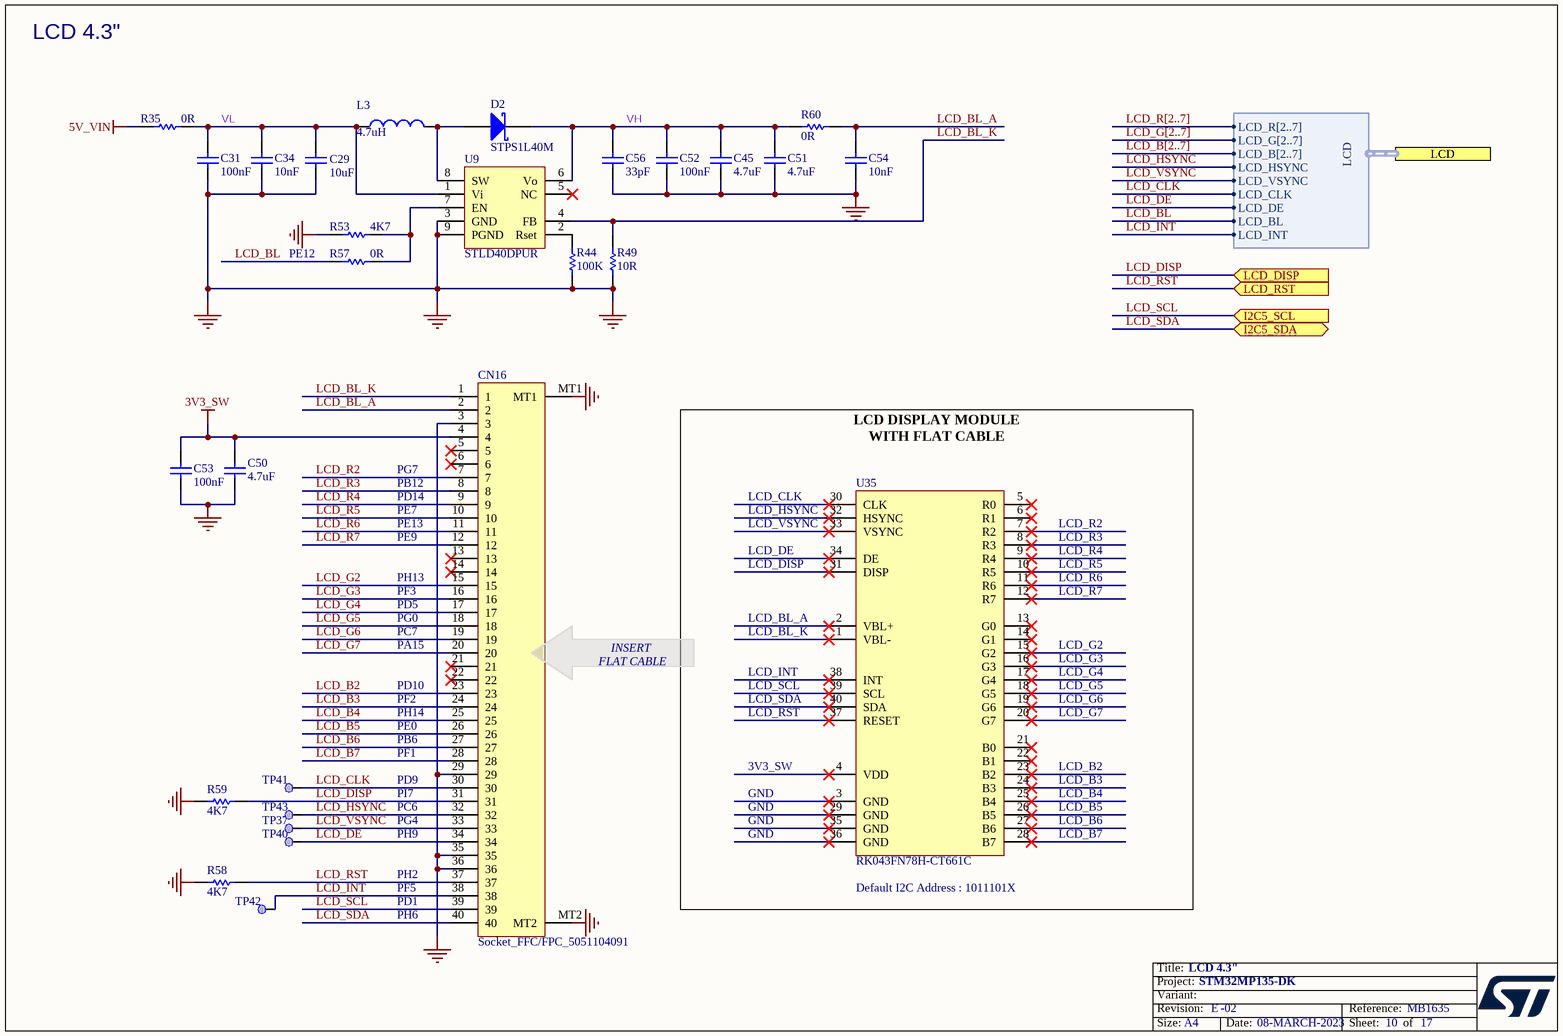
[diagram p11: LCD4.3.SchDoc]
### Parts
C29  value 10uF  [C0603]  (hidden comment: Capacitor)
C31  value 100nF  [C0402]  (hidden comment: Capacitor)
C34  value 10nF  [C0402]  (hidden comment: Capacitor)
C45  value 4.7uF  [C1206_H1P25]  (hidden comment: Capacitor)
C50  value 4.7uF  [C0402]  (hidden comment: Capacitor)
C51  value 4.7uF  [C1206_H1P25]  (hidden comment: Capacitor)
C52  value 100nF  [C0603]  (hidden comment: Capacitor)
C53  value 100nF  [C0402]  (hidden comment: Capacitor)
C54  value 10nF  [C0402]  (hidden comment: Capacitor)
C56  value 33pF  [C0402]  (hidden comment: Capacitor)
CN16  value Socket_FFC/FPC_5051104091  [CON_MOLEX_5051104091]  (hidden comment: 5051104091)
D2  STPS1L40M  [DIO_DO216-AA]
L3  value 4.7uH  [L1210_LQH]  (hidden comment: Inductor)
R35  value 0R  [R0603]  (hidden comment: Resistor)
R44  value 100K  [R0402]  (hidden comment: Resistor)
R49  value 10R  [R0603]  (hidden comment: Resistor)
R53  value 4K7  [R0402]  (hidden comment: Resistor)
R57  value 0R  [R0402]  (hidden comment: Resistor)
R58  value 4K7  [R0402]  (hidden comment: Resistor)
R59  value 4K7  [R0402]  (hidden comment: Resistor)
R60  value 0R  [R0402]  (hidden comment: Resistor)
TP37  Test Point  [TP_SMD_1MM]  (value not drawn)  (no BOM)
TP40  Test Point  [TP_SMD_1MM]  (value not drawn)  (no BOM)
TP41  Test Point  [TP_SMD_1MM]  (value not drawn)  (no BOM)
TP42  Test Point  [TP_SMD_1MM]  (value not drawn)  (no BOM)
TP43  Test Point  [TP_SMD_1MM]  (value not drawn)  (no BOM)
U9  STLD40DPUR  [ICC_QFN8-EPAD_3X3_P065]
U35  RK043FN78H-CT661C  [LCD_DRAWING_ROCKTEK_RK043FN78H-CT661C]

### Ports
I2C5_SCL (in), I2C5_SDA (bidir), LCD (harness LCD), LCD_DISP (in), LCD_RST (in)

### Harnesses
LCD: LCD_R[2..7], LCD_G[2..7], LCD_B[2..7], LCD_HSYNC, LCD_VSYNC, LCD_DE, LCD_CLK, LCD_BL, LCD_INT

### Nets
3V3_SW: C50.1 C53.2 CN16.4
5V_VIN: R35.1
GND: C29.2 C31.1 C34.1 C45.1 C50.2 C51.1 C52.1 C53.1 C54.1 C56.1 CN16.3 CN16.29 CN16.35 CN16.36 CN16.MT1 CN16.MT2 R44.1 R49.1 R53.1 R58.2 R59.1 U9.3(GND) U9.9(PGND)
LCD_B2: CN16.23
LCD_B3: CN16.24
LCD_B4: CN16.25
LCD_B5: CN16.26
LCD_B6: CN16.27
LCD_B7: CN16.28
LCD_BL: R57.1 ; port LCD.LCD_BL
LCD_BL_A: C54.2 CN16.2 R60.2
LCD_BL_K: CN16.1 R49.2 U9.4(FB)
LCD_CLK: CN16.30 TP41.1 ; port LCD.LCD_CLK
LCD_DE: CN16.34 TP40.1 ; port LCD.LCD_DE
LCD_DISP: CN16.31 R59.2 ; port LCD_DISP
LCD_G2: CN16.15
LCD_G3: CN16.16
LCD_G4: CN16.17
LCD_G5: CN16.18
LCD_G6: CN16.19
LCD_G7: CN16.20
LCD_HSYNC: CN16.32 TP43.1 ; port LCD.LCD_HSYNC
LCD_INT: CN16.38 TP42.1 ; port LCD.LCD_INT
LCD_R2: CN16.7
LCD_R3: CN16.8
LCD_R4: CN16.9
LCD_R5: CN16.10
LCD_R6: CN16.11
LCD_R7: CN16.12
LCD_RST: CN16.37 R58.1 ; port LCD_RST
LCD_SCL: CN16.39 ; port I2C5_SCL  [project net EXP_GPIO3]
LCD_SDA: CN16.40 ; port I2C5_SDA  [project net EXP_GPIO2]
LCD_VSYNC: CN16.33 TP37.1 ; port LCD.LCD_VSYNC
VH: C45.2 C51.2 C52.2 C56.2 D2.2(K) R60.1 U9.6(Vo)
VL: C29.1 C31.2 C34.2 L3.1 R35.2 U9.1(Vi)
NetD2_1: D2.1(A) L3.2 U9.8(SW)
NetR44_2: R44.2 U9.2(Rset)
NetR53_2: R53.2 R57.2 U9.7(EN)

Not connected (* = marked no-connect by the designer): CN16 5* 6* 13* 14* 21* 22*; U9 5(NC)*; U35 1(VBL-)* 2(VBL+)* 3(GND)* 4(VDD)* 5(R0)* 6(R1)* 7(R2)* 8(R3)* 9(R4)* 10(R5)* 11(R6)* 12(R7)* 13(G0)* 14(G1)* 15(G2)* 16(G3)* 17(G4)* 18(G5)* 19(G6)* 20(G7)* 21(B0)* 22(B1)* 23(B2)* 24(B3)* 25(B4)* 26(B5)* 27(B6)* 28(B7)* 29(GND)* 30(CLK)* 31(DISP)* 32(HSYNC)* 33(VSYNC)* 34(DE)* 35(GND)* 36(GND)* 37(RESET)* 38(INT)* 39(SCL)* 40(SDA)*

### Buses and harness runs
bus LCD_B[2..7]
bus LCD_G[2..7]
bus LCD_R[2..7]

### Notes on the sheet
- LCD 4.3"
- PE12
- PG7
- PB12
- PD14
- PE7
- LCD_CLK
- (near U35) LCD_HSYNC
- PE13
- PE9
- PH13
- (near U35) LCD_VSYNC
- LCD_DE
- LCD_DISP
- LCD_R2
- LCD_R3
- LCD_R4
- LCD_R5
- LCD_R6
- PF3
- PD5
- PG0
- PC7
- PA15
- (near CN16) INSERT
  FLAT CABLE
- LCD_BL_A
- LCD_BL_K
- LCD_R7
- LCD_G2
- PD10
- PF2
- PH14
- LCD_INT
- LCD_RST
- LCD_SCL
- LCD_SDA
- LCD_G3
- LCD_G4
- LCD_G5
- LCD_G6
- LCD_G7
- PE0
- PB6
- PF1
- PD9
- 3V3_SW
- LCD_B2
- LCD_B3
- PG4
- PC6
- PH9
- PI7
- GND
- LCD_B4
- LCD_B5
- LCD_B6
- LCD_B7
- PH6
- PD1
- PF5
- PH2
- (near U35) LCD DISPLAY MODULE
  WITH FLAT CABLE
- (near U35) Default I2C Address : 1011101X

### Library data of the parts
C29 = MCD-00099: as C27 on sheet Peripherals
C31 C53 = MCD-00006: as C118 on sheet MP135_11x11
C34 C54 = MCD-02198: as C223 on sheet Peripherals
C45 C51 = MCD-00013: Capacitor, MLCC, 4.7uF, 50V, X7R, +/-10%, 1206, T=1.27mm; Manufacturer_Part_Number: 12065C475KAT2A; Manufacturer: AVX; Part_Preference: Recommended; Order_Code_RS: 178-0947; Component_Country_Of_Origin: China, Penang; ShowFields: YES; ID: 2466
C50 = MCD-01356: Capacitor, MLCC, 4.7uF, 6V3, X5R, +/-20%, 0402, T=0.5mm; Manufacturer_Part_Number: GRM155R60J475ME47; Manufacturer: MURATA; Part_Preference: Recommended; Order_Code_RS: 814-5230; Component_Country_Of_Origin: Japan; ShowFields: YES; ID: 3456
C52 = MCD-01099: Capacitor, MLCC, 100nF, 50V, X7R, +/-10%, 0603, T=0.8mm; BMS_Part_Number: 9142278; Part_Preference: Recommended; Manufacturer: YAGEO; Manufacturer_Part_Number: CC0603KRX7R9BB104; Order_Code_RS: 669-8767; Component_Country_Of_Origin: China; ShowFields: YES; ID: 3397
C56 = MCD-00277: Capacitor, MLCC, 33pF, 50V, NPO,+/-5%, 0402, T=0.5mm; Part_Preference: Recommended; Manufacturer: YAGEO; Manufacturer_Part_Number: CC0402JRNPO9BN330; Component_Country_Of_Origin: China; ShowFields: YES; ID: 2592
CN16 = MCD-02589: Socket_FFC/FPC, 40pins, 0.5mm, RA, SMD, T=1.9mm; Part_Type: Connector; Part_Preference: Recommended; Manufacturer: MOLEX; Order_Code_RS: 178-8776; ShowFields: YES; ID: 4695
D2 = MCD-00033: Low Drop power Schottky rectifier(1A, 40V, 0.4V); Part_Type: Diode; Manufacturer: STMICROELECTRONICS; BMS_Part_Number: 9151085; Part_Preference: Recommended; Manufacturer_HQ_COO: EU; Component_Country_Of_Origin: China; ShowFields: YES; ID: 2485
L3 = MCD-00048: Inductor, 4.7uH, +/-30%, 1A, 180mR, 1210, T=1.7mm; Manufacturer_Part_Number: LQH32PN4R7NN0L; Manufacturer: MURATA; Part_Preference: Recommended; Order_Code_RS: 167-4086; Component_Country_Of_Origin: Japan; ShowFields: YES; ID: 2544
R35 = MCD-00181: Resistor, 0R, 0603, +/- 0.5mR, 1/4W; Part_Preference: Recommended; Manufacturer: ROHM; Manufacturer_Part_Number: PMR03EZPJ000; Component_Country_Of_Origin: Philippines, Thailand; ShowFields: YES; ID: 2691
R44 = MCD-00059: Resistor, 100K, 0402, +/-1%, 1/16W; Manufacturer_Part_Number: RC0402FR-07100KL; Manufacturer: YAGEO; Part_Preference: Recommended; Component_Country_Of_Origin: China; ShowFields: YES; ID: 2533
R49 = MCD-00060: Resistor, 10R, 0603, +/-1%, 1/4W; Manufacturer_Part_Number: ESR03EZPF10R0; Manufacturer: ROHM; Part_Preference: Recommended; Order_Code_RS: 167-3753; Component_Country_Of_Origin: Philippines, Thailand; ShowFields: YES; ID: 2531
R53 R58 R59 = MCD-00065: Resistor, 4K7, 0402, +/-1%, 1/16W; Manufacturer_Part_Number: RC0402FR-074K7L; Manufacturer: YAGEO; Part_Preference: Recommended; Component_Country_Of_Origin: China; ShowFields: YES; ID: 2526
R57 = MCD-00052: as R103 on sheet MP135_11x11
R60 = MCD-00052: as R64 on sheet MP135_11x11
TP37 TP40-TP43 = MCD-00074: as TP29 on sheet Peripherals
U9 = MCD-00082: White LED power supply for large display backlight, QFN8; Part_Type: IC; Manufacturer: STMICROELECTRONICS; BMS_Part_Number: 9176009; Part_Preference: Recommended; Manufacturer_HQ_COO: EU; Component_Country_Of_Origin: Malaysia; ShowFields: YES; ID: 2510
U35 = MCD-02422: LCD,  TFT, 4.3 inch, 480x272 pixels with LED Backlight and Capacitive touch panel, high luminance with 0.5mm pitch flat cable; Part_Type: Display; Manufacturer_Part_Number: RK043FN78HV-CT661C; Manufacturer: ROCKTECH; Part_Preference: Recommended; Component_Country_Of_Origin: Unknown; ShowFields: YES; ID: 4528

## Sheet MCP_IO_expander.SchDoc: IO expander
size A4; Project: STM32MP15x-EVAL; Date: Not used; ApprovedBy: Not used; CheckedBy: Not used; Author: Not used; CompanyName: STMicroelectronics; DrawnBy: Not used; Engineer: Not used; Organization: Not used; Address1: Not used; Address2: Not used; Address3: Not used; Address4: Not used; DocumentNumber: 16; Revision: Not used; SheetNumber: 16; SheetTotal: 17

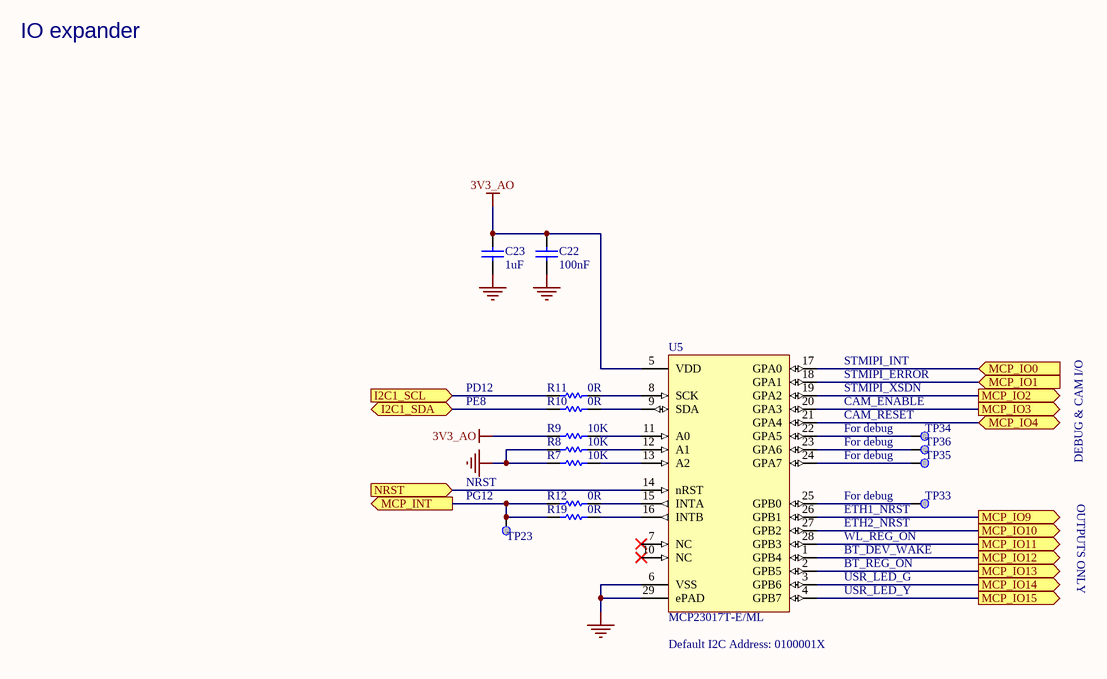
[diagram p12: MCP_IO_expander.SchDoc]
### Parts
C22  value 100nF  [C0402]  (hidden comment: Capacitor)
C23  value 1uF  [C0201_MURATA_GRM033_H0P3]  (hidden comment: Capacitor)
R7  value 10K  [R0402]  (hidden comment: Resistor)
R8  value 10K  [R0402]  (hidden comment: Resistor)
R9  value 10K  [R0402]  (hidden comment: Resistor)
R10  value 0R  [R0402]  (hidden comment: Resistor)
R11  value 0R  [R0402]  (hidden comment: Resistor)
R12  value 0R  [R0402]  (hidden comment: Resistor)
R19  value 0R  [R0402]  (hidden comment: Resistor)
TP23  Test Point  [TP_SMD_1MM]  (value not drawn)  (no BOM)
TP33  Test Point  [TP_SMD_1MM]  (value not drawn)  (no BOM)
TP34  Test Point  [TP_SMD_1MM]  (value not drawn)  (no BOM)
TP35  Test Point  [TP_SMD_1MM]  (value not drawn)  (no BOM)
TP36  Test Point  [TP_SMD_1MM]  (value not drawn)  (no BOM)
U5  value MCP23017T-E/ML  [ICC_QFN28-EPAD_6X6_P065]  (hidden comment: MCP23017)

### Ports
I2C1_SCL (in), I2C1_SDA (bidir), MCP_INT (out), MCP_IO0 (in), MCP_IO1 (in), MCP_IO2 (out), MCP_IO3 (out), MCP_IO4 (bidir), MCP_IO9 (out), MCP_IO10 (out), MCP_IO11 (out), MCP_IO12 (out), MCP_IO13 (out), MCP_IO14 (out), MCP_IO15 (out), NRST (in)

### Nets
3V3_AO: C22.2 C23.2 R9.1 U5.5(VDD)
GND: C22.1 C23.1 R7.1 R8.1 U5.6(VSS) U5.29(ePAD)
I2C1_SCL: R11.1 ; port I2C1_SCL
I2C1_SDA: R10.1 ; port I2C1_SDA
MCP_INT: R12.1 R19.1 TP23.1 ; port MCP_INT
MCP_IO0: U5.17(GPA0) ; port MCP_IO0
MCP_IO1: U5.18(GPA1) ; port MCP_IO1
MCP_IO2: U5.19(GPA2) ; port MCP_IO2
MCP_IO3: U5.20(GPA3) ; port MCP_IO3
MCP_IO4: U5.21(GPA4) ; port MCP_IO4
MCP_IO9: U5.26(GPB1) ; port MCP_IO9
MCP_IO10: U5.27(GPB2) ; port MCP_IO10
MCP_IO11: U5.28(GPB3) ; port MCP_IO11
MCP_IO12: U5.1(GPB4) ; port MCP_IO12
MCP_IO13: U5.2(GPB5) ; port MCP_IO13
MCP_IO14: U5.3(GPB6) ; port MCP_IO14
MCP_IO15: U5.4(GPB7) ; port MCP_IO15
NRST: U5.14(nRST) ; port NRST
NetR7_2: R7.2 U5.13(A2)
NetR8_2: R8.2 U5.12(A1)
NetR9_2: R9.2 U5.11(A0)
NetR10_2: R10.2 U5.9(SDA)
NetR11_2: R11.2 U5.8(SCK)
NetR12_2: R12.2 U5.15(INTA)
NetR19_2: R19.2 U5.16(INTB)
NetTP33_1: TP33.1 U5.25(GPB0)
NetTP34_1: TP34.1 U5.22(GPA5)
NetTP35_1: TP35.1 U5.24(GPA7)
NetTP36_1: TP36.1 U5.23(GPA6)

Not connected (* = marked no-connect by the designer): U5 7(NC)* 10(NC)*

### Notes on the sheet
- IO expander
- STMIPI_INT
- STMIPI_ERROR
- PD12
- PE8
- CAM_RESET
- For debug
- CAM_ENABLE
- STMIPI_XSDN
- (near TP23) PG12
- (near TP23) NRST
- (near TP33) ETH1_NRST
- OUTPUTS ONLY
- DEBUG & CAM I/O
- BT_DEV_WAKE
- BT_REG_ON
- (near TP33) ETH2_NRST
- WL_REG_ON
- USR_LED_G
- (near U5) Default I2C Address: 0100001X
- USR_LED_Y

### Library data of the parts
C22 = MCD-00006: Capacitor, MLCC, 100nF, 16V, X7R, +/-10%, 0402, T=0.5mm; Part_Preference: Recommended; Manufacturer: YAGEO; Manufacturer_Part_Number: CC0402KRX7R7BB104; Order_Code_RS: 616-9701; Component_Country_Of_Origin: China; ShowFields: YES; ID: 2474
C23 = MCD-02377: Capacitor, MLCC, 1uF, 6.3V, X5R, +/-20%, 0201, T=0,3mm; Part_Preference: Recommended; Manufacturer: MURATA; Manufacturer_Part_Number: GRM033R60J105MEA2; Order_Code_RS: 820-0643; Component_Country_Of_Origin: Japan; ShowFields: YES; ID: 4483
R7-R9 = MCD-00053: Resistor, 10K, 0402, +/-1%, 1/16W; BMS_Part_Number: 9131590; Part_Preference: Recommended; Manufacturer: YAGEO; Manufacturer_Part_Number: RC0402FR-0710KL; Component_Country_Of_Origin: China; ShowFields: YES; ID: 2539
R10-R12 R19 = MCD-00052: as R64 on sheet MP135_11x11
TP23 TP33-TP36 = MCD-00074: as TP29 on sheet Peripherals
U5 = MCD-02210: 16-bit port expander with I2C control; Part_Preference: Recommended; Part_Type: IC; Manufacturer: MICROCHIP; Order_code_RS: 177-2846; Component_Country_Of_Origin: Unknown; ShowFields: YES; ID: 4310

## Sheet USB_Host_Hub.SchDoc: USB Host HUB
size A3; Project: STM32MP15-DISCO PI; Date: Not used; ApprovedBy: Not used; CheckedBy: Not used; Author: Not used; CompanyName: STMicroelectronics; DrawnBy: Not used; Engineer: Not used; Organization: Not used; Address1: Not used; Address2: Not used; Address3: Not used; Address4: Not used; DocumentNumber: 12; Revision: Not used; SheetNumber: 12; SheetTotal: 17

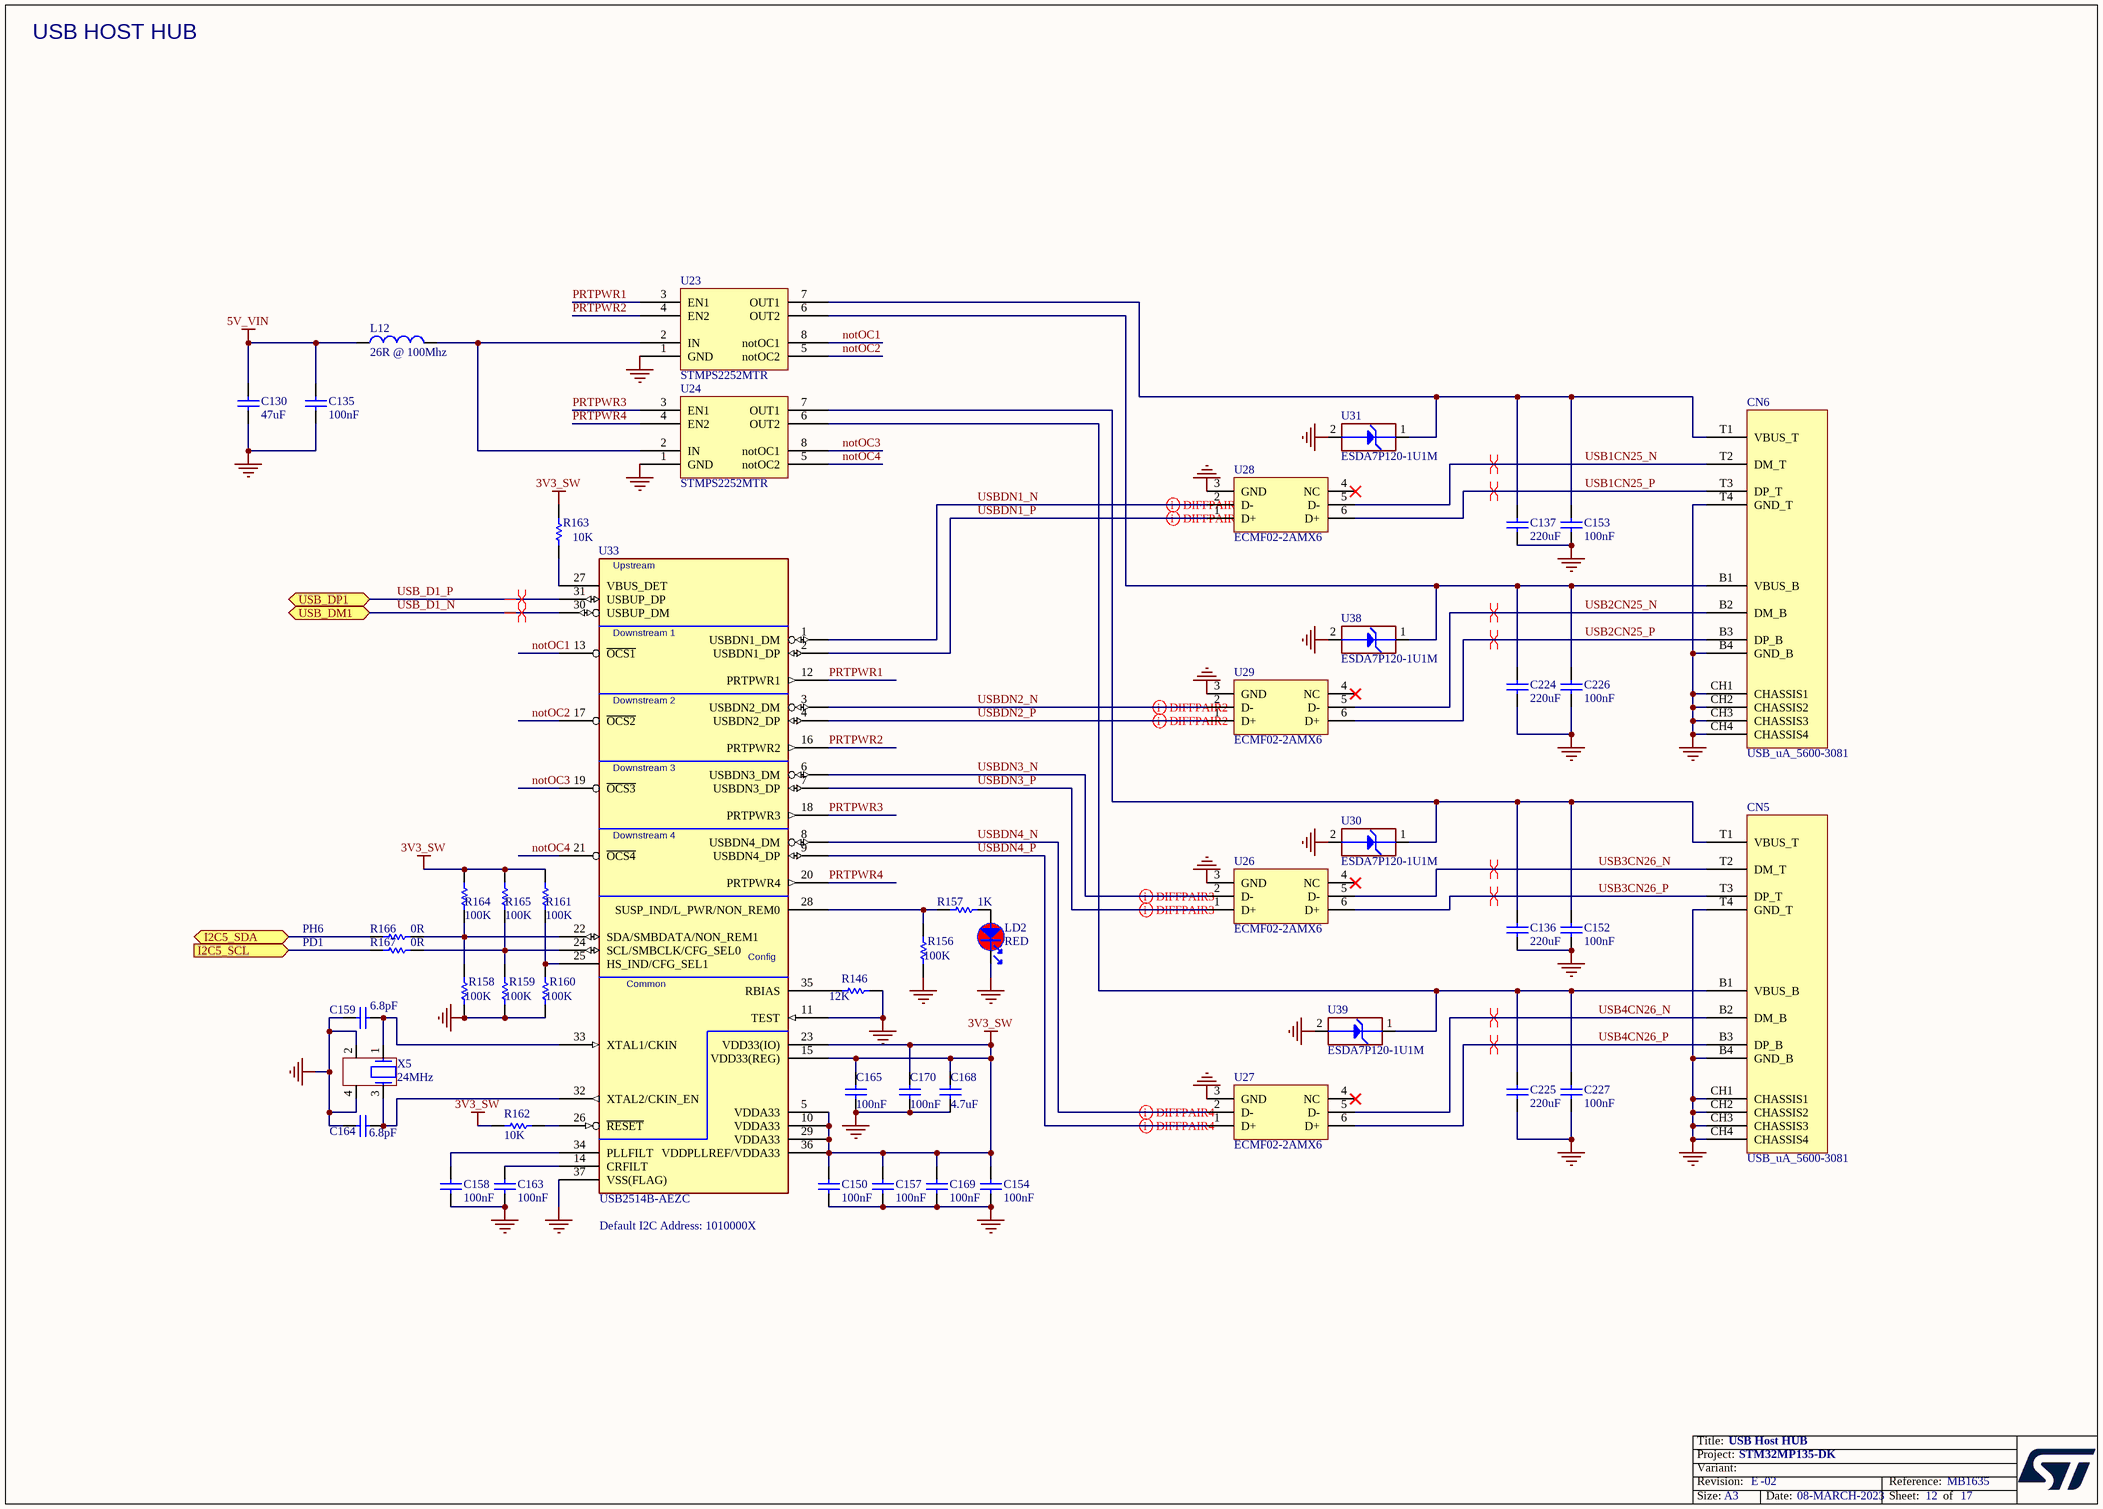
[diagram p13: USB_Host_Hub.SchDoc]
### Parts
C130  value 47uF  [C1206_H1P6]  (hidden comment: Capacitor)
C135  value 100nF  [C0402]  (hidden comment: Capacitor)
C136  value 220uF  [C1206_H1P6]  (hidden comment: Capacitor)
C137  value 220uF  [C1206_H1P6]  (hidden comment: Capacitor)
C150  value 100nF  [C0402]  (hidden comment: Capacitor)
C152  value 100nF  [C0402]  (hidden comment: Capacitor)
C153  value 100nF  [C0402]  (hidden comment: Capacitor)
C154  value 100nF  [C0402]  (hidden comment: Capacitor)
C157  value 100nF  [C0402]  (hidden comment: Capacitor)
C158  value 100nF  [C0402]  (hidden comment: Capacitor)
C159  value 6.8pF  [C0402]  (hidden comment: Capacitor)
C163  value 100nF  [C0402]  (hidden comment: Capacitor)
C164  value 6.8pF  [C0402]  (hidden comment: Capacitor)
C165  value 100nF  [C0402]  (hidden comment: Capacitor)
C168  value 4.7uF  [C0402]  (hidden comment: Capacitor)
C169  value 100nF  [C0402]  (hidden comment: Capacitor)
C170  value 100nF  [C0402]  (hidden comment: Capacitor)
C224  value 220uF  [C1206_H1P6]  (hidden comment: Capacitor)
C225  value 220uF  [C1206_H1P6]  (hidden comment: Capacitor)
C226  value 100nF  [C0402]  (hidden comment: Capacitor)
C227  value 100nF  [C0402]  (hidden comment: Capacitor)
CN5  value USB_uA_5600-3081  [CON_DUAL-USB-TYPE-A_CONEXCON_5600-3081]  (hidden comment: USB_DUAL_TYPEA_5600-3081)
CN6  value USB_uA_5600-3081  [CON_DUAL-USB-TYPE-A_CONEXCON_5600-3081]  (hidden comment: USB_DUAL_TYPEA_5600-3081)
L12  value 26R @ 100Mhz  [FIL_0603_H0P65]  (hidden comment: BEAD)
LD2  value RED  [LED_0603_RED]  (hidden comment: LED_red)
R146  value 12K  [R0402]  (hidden comment: Resistor)
R156  value 100K  [R0402]  (hidden comment: Resistor)
R157  value 1K  [R0402]  (hidden comment: Resistor)
R158  value 100K  [R0402]  (hidden comment: Resistor)
R159  value 100K  [R0402]  (hidden comment: Resistor)
R160  value 100K  [R0402]  (hidden comment: Resistor)
R161  value 100K  [R0402]  (hidden comment: Resistor)
R162  value 10K  [R0402]  (hidden comment: Resistor)
R163  value 10K  [R0402]  (hidden comment: Resistor)
R164  value 100K  [R0402]  (hidden comment: Resistor)
R165  value 100K  [R0402]  (hidden comment: Resistor)
R166  value 0R  [R0402]  (hidden comment: Resistor)
R167  value 0R  [R0402]  (hidden comment: Resistor)
U23  STMPS2252MTR  [ICC_SO8_5X4_P127]
U24  STMPS2252MTR  [ICC_SO8_5X4_P127]
U26  ECMF02-2AMX6  [ESD_QFN-6L_1P7X1P5_P050]
U27  ECMF02-2AMX6  [ESD_QFN-6L_1P7X1P5_P050]
U28  ECMF02-2AMX6  [ESD_QFN-6L_1P7X1P5_P050]
U29  ECMF02-2AMX6  [ESD_QFN-6L_1P7X1P5_P050]
U30  value ESDA7P120-1U1M  [ESD_QFN1610_2N_1K_2A]  (hidden comment: ESD-TRANSIL)
U31  value ESDA7P120-1U1M  [ESD_QFN1610_2N_1K_2A]  (hidden comment: ESD-TRANSIL)
U33  USB2514B-AEZC  [ICC_QFN36-EPAD_6X6_P050]
U38  value ESDA7P120-1U1M  [ESD_QFN1610_2N_1K_2A]  (hidden comment: ESD-TRANSIL)
U39  value ESDA7P120-1U1M  [ESD_QFN1610_2N_1K_2A]  (hidden comment: ESD-TRANSIL)
X5  value 24MHz  [CRY_NX2016SA_4P]  (hidden comment: XTAL_4_PINS)

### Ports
I2C5_SCL (in), I2C5_SDA (bidir), USB_DM1 (bidir), USB_DP1 (bidir)

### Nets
3V3_SW: C150.2 C154.2 C157.2 C165.2 C168.2 C169.2 C170.2 R161.2 R162.1 R163.2 R164.2 R165.2 U33.5(VDDA33) U33.10(VDDA33) U33.15(VDD33(REG)) U33.23(VDD33(IO)) U33.29(VDDA33) U33.36(VDDPLLREF/VDDA33)
5V_VIN: C130.2 C135.2 L12.1
GND: C130.1 C135.1 C136.1 C137.1 C150.1 C152.1 C153.1 C154.1 C157.1 C158.1 C159.1 C163.1 C164.1 C165.1 C168.1 C169.1 C170.1 C224.1 C225.1 C226.1 C227.1 CN5.B4(GND_B) CN5.CH1(CHASSIS1) CN5.CH2(CHASSIS2) CN5.CH3(CHASSIS3) CN5.CH4(CHASSIS4) CN5.T4(GND_T) CN6.B4(GND_B) CN6.CH1(CHASSIS1) CN6.CH2(CHASSIS2) CN6.CH3(CHASSIS3) CN6.CH4(CHASSIS4) CN6.T4(GND_T) LD2.2 R146.1 R156.1 R158.1 R159.1 R160.1 U23.1(GND) U24.1(GND) U26.3(GND) U27.3(GND) U28.3(GND) U29.3(GND) U30.2(GND) U31.2(GND) U33.11(TEST) U33.37(VSS(FLAG)) U38.2(GND) U39.2(GND) X5.2 X5.4
EXP_GPIO2: R166.1 ; port I2C5_SDA
EXP_GPIO3: R167.1 ; port I2C5_SCL
notOC1: U23.8(notOC1) U33.13(~{OCS1})
notOC2: U23.5(notOC2) U33.17(~{OCS2})
notOC3: U24.8(notOC1) U33.19(~{OCS3})
notOC4: U24.5(notOC2) U33.21(~{OCS4})
PRTPWR1: U23.3(EN1) U33.12(PRTPWR1)
PRTPWR2: U23.4(EN2) U33.16(PRTPWR2)
PRTPWR3: U24.3(EN1) U33.18(PRTPWR3)
PRTPWR4: U24.4(EN2) U33.20(PRTPWR4)
USB1CN25_N: CN6.T2(DM_T) U28.5(D-)
USB1CN25_P: CN6.T3(DP_T) U28.6(D+)
USB2CN25_N: CN6.B2(DM_B) U29.5(D-)
USB2CN25_P: CN6.B3(DP_B) U29.6(D+)
USB3CN26_N: CN5.T2(DM_T) U26.5(D-)
USB3CN26_P: CN5.T3(DP_T) U26.6(D+)
USB4CN26_N: CN5.B2(DM_B) U27.5(D-)
USB4CN26_P: CN5.B3(DP_B) U27.6(D+)
USB_D1_N: U33.30(USBUP_DM) ; port USB_DM1
USB_D1_P: U33.31(USBUP_DP) ; port USB_DP1
USBDN1_N: U28.2(D-) U33.1(USBDN1_DM)
USBDN1_P: U28.1(D+) U33.2(USBDN1_DP)
USBDN2_N: U29.2(D-) U33.3(USBDN2_DM)
USBDN2_P: U29.1(D+) U33.4(USBDN2_DP)
USBDN3_N: U26.2(D-) U33.6(USBDN3_DM)
USBDN3_P: U26.1(D+) U33.7(USBDN3_DP)
USBDN4_N: U27.2(D-) U33.8(USBDN4_DM)
USBDN4_P: U27.1(D+) U33.9(USBDN4_DP)
NetC136_2: C136.2 C152.2 CN5.T1(VBUS_T) U24.7(OUT1) U30.1(IO1)
NetC137_2: C137.2 C153.2 CN6.T1(VBUS_T) U23.7(OUT1) U31.1(IO1)
NetC158_2: C158.2 U33.34(PLLFILT)
NetC159_2: C159.2 U33.33(XTAL1/CKIN) X5.1
NetC163_2: C163.2 U33.14(CRFILT)
NetC164_2: C164.2 U33.32(XTAL2/CKIN_EN) X5.3
NetC224_2: C224.2 C226.2 CN6.B1(VBUS_B) U23.6(OUT2) U38.1(IO1)
NetC225_2: C225.2 C227.2 CN5.B1(VBUS_B) U24.6(OUT2) U39.1(IO1)
NetL12_2: L12.2 U23.2(IN) U24.2(IN)
NetLD2_1: LD2.1 R157.1
NetR146_2: R146.2 U33.35(RBIAS)
NetR156_2: R156.2 R157.2 U33.28(SUSP_IND/L_PWR/NON_REM0)
NetR158_2: R158.2 R164.1 R166.2 U33.22(SDA/SMBDATA/NON_REM1)
NetR159_2: R159.2 R165.1 R167.2 U33.24(SCL/SMBCLK/CFG_SEL0)
NetR160_2: R160.2 R161.1 U33.25(HS_IND/CFG_SEL1)
NetR162_2: R162.2 U33.26(~{RESET})
NetR163_1: R163.1 U33.27(VBUS_DET)

Not connected (* = marked no-connect by the designer): U26 4(NC)*; U27 4(NC)*; U28 4(NC)*; U29 4(NC)*

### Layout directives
differential pair: USB1CN25_N, USB1CN25_P, USB2CN25_N, USB2CN25_P, USB3CN26_N, USB3CN26_P, USB4CN26_N, USB4CN26_P, USB_D1_N, USB_D1_P, USBDN1_N, USBDN1_P, USBDN2_N, USBDN2_P, USBDN3_N, USBDN3_P, USBDN4_N, USBDN4_P

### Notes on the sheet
- USB HOST HUB
- PH6
- PD1
- Default I2C Address: 1010000X

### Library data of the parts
C130 = MCD-02263: Capacitor, MLCC, 47uF, 25V, X5R, 20%, 1206, T=1.6mm; Part_Preference: Recommended; Manufacturer: MURATA; Manufacturer_Part_Number: GRM31CR61E476ME44; Component_Country_Of_Origin: Japan; ShowFields: YES; ID: 4363
C135 C150 C152-C154 C157 C158 C163 C165 C169 C170 C226 C227 = MCD-00006: as C118 on sheet MP135_11x11
C136 C137 C224 C225 = MCD-00104: Capacitor, MLCC, 220uF, 6V3, X5R, +/-20%, 1206, T=1.6mm; Manufacturer_Part_Number: GRM31CR60J227ME11; Manufacturer: MURATA; Part_Preference: Recommended; Order_Code_RS: 170-6396; Component_Country_Of_Origin: Japan; ShowFields: YES; ID: 2764
C159 C164 = MCD-00674: as C88 on sheet MP135_11x11
C168 = MCD-01356: as C50 on sheet LCD4.3
CN5 CN6 = MCD-00109: USB_Dual-TypeA, Receptacle, 8pins, 2.5mm, RA, TH, T= 15.5mm; Manufacturer: CONEXCON; Part_Type: Connector; Part_Preference: Recommended; Component_Country_Of_Origin: Unknown; ShowFields: YES; ID: 2756
L12 = MCD-00305: Ferrite bead, 26R @ 100Mhz, +/-25%, 6000mA, 0R007, 0603, T=0.75mm; Manufacturer_Part_Number: BLM18KG260TN1; Manufacturer: MURATA; Part_Type: Inductor; Part_Preference: Recommended; Order_Code_RS: 747-4723; Component_Country_Of_Origin: Japan; ShowFields: YES; ID: 2564
LD2 = MCD-00049: as LD4 on sheet Peripherals
R146 = MCD-00187: Resistor, 12K, 0402, +/-1%, 1/16W; Manufacturer_Part_Number: RC0402FR-0712KL; Manufacturer: YAGEO; BMS_Part_Number: 9131030; Part_Preference: Recommended; Component_Country_Of_Origin: China; ShowFields: YES; ID: 2678
R156 R158-R161 R164 R165 = MCD-00059: as R44 on sheet LCD4.3
R157 = MCD-00061: as R153 on sheet Peripherals
R162 R163 = MCD-00053: as R33 on sheet Peripherals
R166 R167 = MCD-00052: as R64 on sheet MP135_11x11
U23 U24 = MCD-00123: IC,Dual-Channel-Power-Switch,500mA,100mR,SO8; Manufacturer: STMICROELECTRONICS; BMS_Part_Number: 9159012; Part_Preference: Recommended; Manufacturer_HQ_COO: EU; Component_Country_Of_Origin: China; ShowFields: YES; ID: 2746
U26-U29 = MCD-00649: Common mode filter with ESD protection for USB 2.0 interface; Part_Type: Diode; Manufacturer: STMICROELECTRONICS; BMS_Part_Number: 9151138; Part_Preference: Recommended; Manufacturer_HQ_COO: EU; Component_Country_Of_Origin: China; ShowFields: YES; ID: 3094
U30 U31 U38 U39 = MCD-01026: High power transient voltage suppressor; Part_Type: Diode; Manufacturer: STMICROELECTRONICS; BMS_Part_Number: 9179046; Part_Preference: Recommended; Manufacturer_HQ_COO: EU; Component_Country_Of_Origin: China; ShowFields: YES; ID: 2997
U33 = MCD-00145: USB HUB 2,0 Controller; Manufacturer: MICROCHIP; Part_Type: IC; Part_Preference: Recommended; Component_Country_Of_Origin: Unknown; ShowFields: YES; ID: 2724
X5 = MCD-01036: Crystal, 24MHz, 6pF, +/-20ppm, 80R, 2x1.6mm; Part_Type: Crystal_Osc; Manufacturer_Part_Number: NX2016SA-24MHZ-EXS00A-CS10820; Manufacturer: NDK; BMS_Part_Number: 9157045; Part_Preference: Recommended; Component_Country_Of_Origin: Unknown; ShowFields: YES; ID: 2989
